VERSION 5.7 ;
BUSBITCHARS "[]" ;
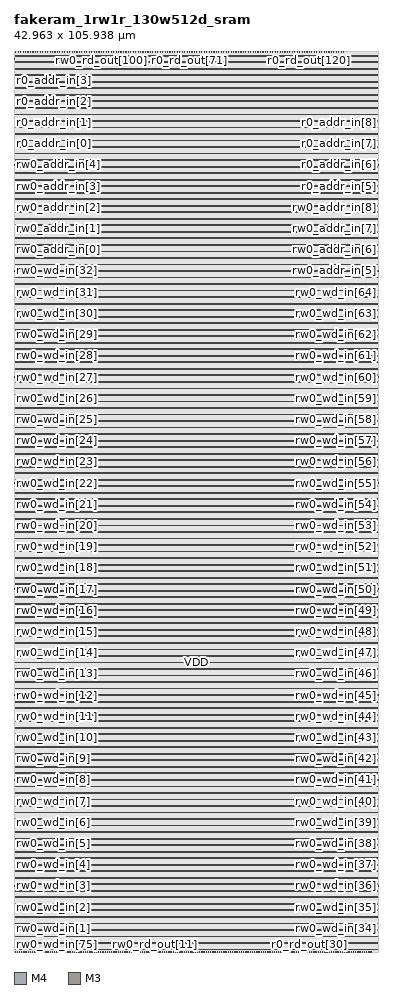
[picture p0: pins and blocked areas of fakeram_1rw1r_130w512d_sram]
MACRO fakeram_1rw1r_130w512d_sram
  FOREIGN fakeram_1rw1r_130w512d_sram 0 0 ;
  SYMMETRY X Y R90 ;
  SIZE 42.963 BY 105.938 ;
  CLASS BLOCK ;
  PIN rw0_wd_in[0]
    DIRECTION INPUT ;
    USE SIGNAL ;
    SHAPE ABUTMENT ;
    PORT
      LAYER M4 ;
      RECT 0.000 0.276 0.072 0.300 ;
    END
  END rw0_wd_in[0]
  PIN rw0_wd_in[1]
    DIRECTION INPUT ;
    USE SIGNAL ;
    SHAPE ABUTMENT ;
    PORT
      LAYER M4 ;
      RECT 0.000 2.772 0.072 2.796 ;
    END
  END rw0_wd_in[1]
  PIN rw0_wd_in[2]
    DIRECTION INPUT ;
    USE SIGNAL ;
    SHAPE ABUTMENT ;
    PORT
      LAYER M4 ;
      RECT 0.000 5.268 0.072 5.292 ;
    END
  END rw0_wd_in[2]
  PIN rw0_wd_in[3]
    DIRECTION INPUT ;
    USE SIGNAL ;
    SHAPE ABUTMENT ;
    PORT
      LAYER M4 ;
      RECT 0.000 7.764 0.072 7.788 ;
    END
  END rw0_wd_in[3]
  PIN rw0_wd_in[4]
    DIRECTION INPUT ;
    USE SIGNAL ;
    SHAPE ABUTMENT ;
    PORT
      LAYER M4 ;
      RECT 0.000 10.260 0.072 10.284 ;
    END
  END rw0_wd_in[4]
  PIN rw0_wd_in[5]
    DIRECTION INPUT ;
    USE SIGNAL ;
    SHAPE ABUTMENT ;
    PORT
      LAYER M4 ;
      RECT 0.000 12.756 0.072 12.780 ;
    END
  END rw0_wd_in[5]
  PIN rw0_wd_in[6]
    DIRECTION INPUT ;
    USE SIGNAL ;
    SHAPE ABUTMENT ;
    PORT
      LAYER M4 ;
      RECT 0.000 15.252 0.072 15.276 ;
    END
  END rw0_wd_in[6]
  PIN rw0_wd_in[7]
    DIRECTION INPUT ;
    USE SIGNAL ;
    SHAPE ABUTMENT ;
    PORT
      LAYER M4 ;
      RECT 0.000 17.748 0.072 17.772 ;
    END
  END rw0_wd_in[7]
  PIN rw0_wd_in[8]
    DIRECTION INPUT ;
    USE SIGNAL ;
    SHAPE ABUTMENT ;
    PORT
      LAYER M4 ;
      RECT 0.000 20.244 0.072 20.268 ;
    END
  END rw0_wd_in[8]
  PIN rw0_wd_in[9]
    DIRECTION INPUT ;
    USE SIGNAL ;
    SHAPE ABUTMENT ;
    PORT
      LAYER M4 ;
      RECT 0.000 22.740 0.072 22.764 ;
    END
  END rw0_wd_in[9]
  PIN rw0_wd_in[10]
    DIRECTION INPUT ;
    USE SIGNAL ;
    SHAPE ABUTMENT ;
    PORT
      LAYER M4 ;
      RECT 0.000 25.236 0.072 25.260 ;
    END
  END rw0_wd_in[10]
  PIN rw0_wd_in[11]
    DIRECTION INPUT ;
    USE SIGNAL ;
    SHAPE ABUTMENT ;
    PORT
      LAYER M4 ;
      RECT 0.000 27.732 0.072 27.756 ;
    END
  END rw0_wd_in[11]
  PIN rw0_wd_in[12]
    DIRECTION INPUT ;
    USE SIGNAL ;
    SHAPE ABUTMENT ;
    PORT
      LAYER M4 ;
      RECT 0.000 30.228 0.072 30.252 ;
    END
  END rw0_wd_in[12]
  PIN rw0_wd_in[13]
    DIRECTION INPUT ;
    USE SIGNAL ;
    SHAPE ABUTMENT ;
    PORT
      LAYER M4 ;
      RECT 0.000 32.724 0.072 32.748 ;
    END
  END rw0_wd_in[13]
  PIN rw0_wd_in[14]
    DIRECTION INPUT ;
    USE SIGNAL ;
    SHAPE ABUTMENT ;
    PORT
      LAYER M4 ;
      RECT 0.000 35.220 0.072 35.244 ;
    END
  END rw0_wd_in[14]
  PIN rw0_wd_in[15]
    DIRECTION INPUT ;
    USE SIGNAL ;
    SHAPE ABUTMENT ;
    PORT
      LAYER M4 ;
      RECT 0.000 37.716 0.072 37.740 ;
    END
  END rw0_wd_in[15]
  PIN rw0_wd_in[16]
    DIRECTION INPUT ;
    USE SIGNAL ;
    SHAPE ABUTMENT ;
    PORT
      LAYER M4 ;
      RECT 0.000 40.212 0.072 40.236 ;
    END
  END rw0_wd_in[16]
  PIN rw0_wd_in[17]
    DIRECTION INPUT ;
    USE SIGNAL ;
    SHAPE ABUTMENT ;
    PORT
      LAYER M4 ;
      RECT 0.000 42.708 0.072 42.732 ;
    END
  END rw0_wd_in[17]
  PIN rw0_wd_in[18]
    DIRECTION INPUT ;
    USE SIGNAL ;
    SHAPE ABUTMENT ;
    PORT
      LAYER M4 ;
      RECT 0.000 45.204 0.072 45.228 ;
    END
  END rw0_wd_in[18]
  PIN rw0_wd_in[19]
    DIRECTION INPUT ;
    USE SIGNAL ;
    SHAPE ABUTMENT ;
    PORT
      LAYER M4 ;
      RECT 0.000 47.700 0.072 47.724 ;
    END
  END rw0_wd_in[19]
  PIN rw0_wd_in[20]
    DIRECTION INPUT ;
    USE SIGNAL ;
    SHAPE ABUTMENT ;
    PORT
      LAYER M4 ;
      RECT 0.000 50.196 0.072 50.220 ;
    END
  END rw0_wd_in[20]
  PIN rw0_wd_in[21]
    DIRECTION INPUT ;
    USE SIGNAL ;
    SHAPE ABUTMENT ;
    PORT
      LAYER M4 ;
      RECT 0.000 52.692 0.072 52.716 ;
    END
  END rw0_wd_in[21]
  PIN rw0_wd_in[22]
    DIRECTION INPUT ;
    USE SIGNAL ;
    SHAPE ABUTMENT ;
    PORT
      LAYER M4 ;
      RECT 0.000 55.188 0.072 55.212 ;
    END
  END rw0_wd_in[22]
  PIN rw0_wd_in[23]
    DIRECTION INPUT ;
    USE SIGNAL ;
    SHAPE ABUTMENT ;
    PORT
      LAYER M4 ;
      RECT 0.000 57.684 0.072 57.708 ;
    END
  END rw0_wd_in[23]
  PIN rw0_wd_in[24]
    DIRECTION INPUT ;
    USE SIGNAL ;
    SHAPE ABUTMENT ;
    PORT
      LAYER M4 ;
      RECT 0.000 60.180 0.072 60.204 ;
    END
  END rw0_wd_in[24]
  PIN rw0_wd_in[25]
    DIRECTION INPUT ;
    USE SIGNAL ;
    SHAPE ABUTMENT ;
    PORT
      LAYER M4 ;
      RECT 0.000 62.676 0.072 62.700 ;
    END
  END rw0_wd_in[25]
  PIN rw0_wd_in[26]
    DIRECTION INPUT ;
    USE SIGNAL ;
    SHAPE ABUTMENT ;
    PORT
      LAYER M4 ;
      RECT 0.000 65.172 0.072 65.196 ;
    END
  END rw0_wd_in[26]
  PIN rw0_wd_in[27]
    DIRECTION INPUT ;
    USE SIGNAL ;
    SHAPE ABUTMENT ;
    PORT
      LAYER M4 ;
      RECT 0.000 67.668 0.072 67.692 ;
    END
  END rw0_wd_in[27]
  PIN rw0_wd_in[28]
    DIRECTION INPUT ;
    USE SIGNAL ;
    SHAPE ABUTMENT ;
    PORT
      LAYER M4 ;
      RECT 0.000 70.164 0.072 70.188 ;
    END
  END rw0_wd_in[28]
  PIN rw0_wd_in[29]
    DIRECTION INPUT ;
    USE SIGNAL ;
    SHAPE ABUTMENT ;
    PORT
      LAYER M4 ;
      RECT 0.000 72.660 0.072 72.684 ;
    END
  END rw0_wd_in[29]
  PIN rw0_wd_in[30]
    DIRECTION INPUT ;
    USE SIGNAL ;
    SHAPE ABUTMENT ;
    PORT
      LAYER M4 ;
      RECT 0.000 75.156 0.072 75.180 ;
    END
  END rw0_wd_in[30]
  PIN rw0_wd_in[31]
    DIRECTION INPUT ;
    USE SIGNAL ;
    SHAPE ABUTMENT ;
    PORT
      LAYER M4 ;
      RECT 0.000 77.652 0.072 77.676 ;
    END
  END rw0_wd_in[31]
  PIN rw0_wd_in[32]
    DIRECTION INPUT ;
    USE SIGNAL ;
    SHAPE ABUTMENT ;
    PORT
      LAYER M4 ;
      RECT 0.000 80.148 0.072 80.172 ;
    END
  END rw0_wd_in[32]
  PIN rw0_wd_in[33]
    DIRECTION INPUT ;
    USE SIGNAL ;
    SHAPE ABUTMENT ;
    PORT
      LAYER M4 ;
      RECT 42.891 0.276 42.963 0.300 ;
    END
  END rw0_wd_in[33]
  PIN rw0_wd_in[34]
    DIRECTION INPUT ;
    USE SIGNAL ;
    SHAPE ABUTMENT ;
    PORT
      LAYER M4 ;
      RECT 42.891 2.772 42.963 2.796 ;
    END
  END rw0_wd_in[34]
  PIN rw0_wd_in[35]
    DIRECTION INPUT ;
    USE SIGNAL ;
    SHAPE ABUTMENT ;
    PORT
      LAYER M4 ;
      RECT 42.891 5.268 42.963 5.292 ;
    END
  END rw0_wd_in[35]
  PIN rw0_wd_in[36]
    DIRECTION INPUT ;
    USE SIGNAL ;
    SHAPE ABUTMENT ;
    PORT
      LAYER M4 ;
      RECT 42.891 7.764 42.963 7.788 ;
    END
  END rw0_wd_in[36]
  PIN rw0_wd_in[37]
    DIRECTION INPUT ;
    USE SIGNAL ;
    SHAPE ABUTMENT ;
    PORT
      LAYER M4 ;
      RECT 42.891 10.260 42.963 10.284 ;
    END
  END rw0_wd_in[37]
  PIN rw0_wd_in[38]
    DIRECTION INPUT ;
    USE SIGNAL ;
    SHAPE ABUTMENT ;
    PORT
      LAYER M4 ;
      RECT 42.891 12.756 42.963 12.780 ;
    END
  END rw0_wd_in[38]
  PIN rw0_wd_in[39]
    DIRECTION INPUT ;
    USE SIGNAL ;
    SHAPE ABUTMENT ;
    PORT
      LAYER M4 ;
      RECT 42.891 15.252 42.963 15.276 ;
    END
  END rw0_wd_in[39]
  PIN rw0_wd_in[40]
    DIRECTION INPUT ;
    USE SIGNAL ;
    SHAPE ABUTMENT ;
    PORT
      LAYER M4 ;
      RECT 42.891 17.748 42.963 17.772 ;
    END
  END rw0_wd_in[40]
  PIN rw0_wd_in[41]
    DIRECTION INPUT ;
    USE SIGNAL ;
    SHAPE ABUTMENT ;
    PORT
      LAYER M4 ;
      RECT 42.891 20.244 42.963 20.268 ;
    END
  END rw0_wd_in[41]
  PIN rw0_wd_in[42]
    DIRECTION INPUT ;
    USE SIGNAL ;
    SHAPE ABUTMENT ;
    PORT
      LAYER M4 ;
      RECT 42.891 22.740 42.963 22.764 ;
    END
  END rw0_wd_in[42]
  PIN rw0_wd_in[43]
    DIRECTION INPUT ;
    USE SIGNAL ;
    SHAPE ABUTMENT ;
    PORT
      LAYER M4 ;
      RECT 42.891 25.236 42.963 25.260 ;
    END
  END rw0_wd_in[43]
  PIN rw0_wd_in[44]
    DIRECTION INPUT ;
    USE SIGNAL ;
    SHAPE ABUTMENT ;
    PORT
      LAYER M4 ;
      RECT 42.891 27.732 42.963 27.756 ;
    END
  END rw0_wd_in[44]
  PIN rw0_wd_in[45]
    DIRECTION INPUT ;
    USE SIGNAL ;
    SHAPE ABUTMENT ;
    PORT
      LAYER M4 ;
      RECT 42.891 30.228 42.963 30.252 ;
    END
  END rw0_wd_in[45]
  PIN rw0_wd_in[46]
    DIRECTION INPUT ;
    USE SIGNAL ;
    SHAPE ABUTMENT ;
    PORT
      LAYER M4 ;
      RECT 42.891 32.724 42.963 32.748 ;
    END
  END rw0_wd_in[46]
  PIN rw0_wd_in[47]
    DIRECTION INPUT ;
    USE SIGNAL ;
    SHAPE ABUTMENT ;
    PORT
      LAYER M4 ;
      RECT 42.891 35.220 42.963 35.244 ;
    END
  END rw0_wd_in[47]
  PIN rw0_wd_in[48]
    DIRECTION INPUT ;
    USE SIGNAL ;
    SHAPE ABUTMENT ;
    PORT
      LAYER M4 ;
      RECT 42.891 37.716 42.963 37.740 ;
    END
  END rw0_wd_in[48]
  PIN rw0_wd_in[49]
    DIRECTION INPUT ;
    USE SIGNAL ;
    SHAPE ABUTMENT ;
    PORT
      LAYER M4 ;
      RECT 42.891 40.212 42.963 40.236 ;
    END
  END rw0_wd_in[49]
  PIN rw0_wd_in[50]
    DIRECTION INPUT ;
    USE SIGNAL ;
    SHAPE ABUTMENT ;
    PORT
      LAYER M4 ;
      RECT 42.891 42.708 42.963 42.732 ;
    END
  END rw0_wd_in[50]
  PIN rw0_wd_in[51]
    DIRECTION INPUT ;
    USE SIGNAL ;
    SHAPE ABUTMENT ;
    PORT
      LAYER M4 ;
      RECT 42.891 45.204 42.963 45.228 ;
    END
  END rw0_wd_in[51]
  PIN rw0_wd_in[52]
    DIRECTION INPUT ;
    USE SIGNAL ;
    SHAPE ABUTMENT ;
    PORT
      LAYER M4 ;
      RECT 42.891 47.700 42.963 47.724 ;
    END
  END rw0_wd_in[52]
  PIN rw0_wd_in[53]
    DIRECTION INPUT ;
    USE SIGNAL ;
    SHAPE ABUTMENT ;
    PORT
      LAYER M4 ;
      RECT 42.891 50.196 42.963 50.220 ;
    END
  END rw0_wd_in[53]
  PIN rw0_wd_in[54]
    DIRECTION INPUT ;
    USE SIGNAL ;
    SHAPE ABUTMENT ;
    PORT
      LAYER M4 ;
      RECT 42.891 52.692 42.963 52.716 ;
    END
  END rw0_wd_in[54]
  PIN rw0_wd_in[55]
    DIRECTION INPUT ;
    USE SIGNAL ;
    SHAPE ABUTMENT ;
    PORT
      LAYER M4 ;
      RECT 42.891 55.188 42.963 55.212 ;
    END
  END rw0_wd_in[55]
  PIN rw0_wd_in[56]
    DIRECTION INPUT ;
    USE SIGNAL ;
    SHAPE ABUTMENT ;
    PORT
      LAYER M4 ;
      RECT 42.891 57.684 42.963 57.708 ;
    END
  END rw0_wd_in[56]
  PIN rw0_wd_in[57]
    DIRECTION INPUT ;
    USE SIGNAL ;
    SHAPE ABUTMENT ;
    PORT
      LAYER M4 ;
      RECT 42.891 60.180 42.963 60.204 ;
    END
  END rw0_wd_in[57]
  PIN rw0_wd_in[58]
    DIRECTION INPUT ;
    USE SIGNAL ;
    SHAPE ABUTMENT ;
    PORT
      LAYER M4 ;
      RECT 42.891 62.676 42.963 62.700 ;
    END
  END rw0_wd_in[58]
  PIN rw0_wd_in[59]
    DIRECTION INPUT ;
    USE SIGNAL ;
    SHAPE ABUTMENT ;
    PORT
      LAYER M4 ;
      RECT 42.891 65.172 42.963 65.196 ;
    END
  END rw0_wd_in[59]
  PIN rw0_wd_in[60]
    DIRECTION INPUT ;
    USE SIGNAL ;
    SHAPE ABUTMENT ;
    PORT
      LAYER M4 ;
      RECT 42.891 67.668 42.963 67.692 ;
    END
  END rw0_wd_in[60]
  PIN rw0_wd_in[61]
    DIRECTION INPUT ;
    USE SIGNAL ;
    SHAPE ABUTMENT ;
    PORT
      LAYER M4 ;
      RECT 42.891 70.164 42.963 70.188 ;
    END
  END rw0_wd_in[61]
  PIN rw0_wd_in[62]
    DIRECTION INPUT ;
    USE SIGNAL ;
    SHAPE ABUTMENT ;
    PORT
      LAYER M4 ;
      RECT 42.891 72.660 42.963 72.684 ;
    END
  END rw0_wd_in[62]
  PIN rw0_wd_in[63]
    DIRECTION INPUT ;
    USE SIGNAL ;
    SHAPE ABUTMENT ;
    PORT
      LAYER M4 ;
      RECT 42.891 75.156 42.963 75.180 ;
    END
  END rw0_wd_in[63]
  PIN rw0_wd_in[64]
    DIRECTION INPUT ;
    USE SIGNAL ;
    SHAPE ABUTMENT ;
    PORT
      LAYER M4 ;
      RECT 42.891 77.652 42.963 77.676 ;
    END
  END rw0_wd_in[64]
  PIN rw0_wd_in[65]
    DIRECTION OUTPUT ;
    USE SIGNAL ;
    SHAPE ABUTMENT ;
    PORT
      LAYER M3 ;
      RECT 0.207 0.000 0.225 0.054 ;
    END
  END rw0_wd_in[65]
  PIN rw0_wd_in[66]
    DIRECTION OUTPUT ;
    USE SIGNAL ;
    SHAPE ABUTMENT ;
    PORT
      LAYER M3 ;
      RECT 0.423 0.000 0.441 0.054 ;
    END
  END rw0_wd_in[66]
  PIN rw0_wd_in[67]
    DIRECTION OUTPUT ;
    USE SIGNAL ;
    SHAPE ABUTMENT ;
    PORT
      LAYER M3 ;
      RECT 0.639 0.000 0.657 0.054 ;
    END
  END rw0_wd_in[67]
  PIN rw0_wd_in[68]
    DIRECTION OUTPUT ;
    USE SIGNAL ;
    SHAPE ABUTMENT ;
    PORT
      LAYER M3 ;
      RECT 0.855 0.000 0.873 0.054 ;
    END
  END rw0_wd_in[68]
  PIN rw0_wd_in[69]
    DIRECTION OUTPUT ;
    USE SIGNAL ;
    SHAPE ABUTMENT ;
    PORT
      LAYER M3 ;
      RECT 1.071 0.000 1.089 0.054 ;
    END
  END rw0_wd_in[69]
  PIN rw0_wd_in[70]
    DIRECTION OUTPUT ;
    USE SIGNAL ;
    SHAPE ABUTMENT ;
    PORT
      LAYER M3 ;
      RECT 1.287 0.000 1.305 0.054 ;
    END
  END rw0_wd_in[70]
  PIN rw0_wd_in[71]
    DIRECTION OUTPUT ;
    USE SIGNAL ;
    SHAPE ABUTMENT ;
    PORT
      LAYER M3 ;
      RECT 1.503 0.000 1.521 0.054 ;
    END
  END rw0_wd_in[71]
  PIN rw0_wd_in[72]
    DIRECTION OUTPUT ;
    USE SIGNAL ;
    SHAPE ABUTMENT ;
    PORT
      LAYER M3 ;
      RECT 1.719 0.000 1.737 0.054 ;
    END
  END rw0_wd_in[72]
  PIN rw0_wd_in[73]
    DIRECTION OUTPUT ;
    USE SIGNAL ;
    SHAPE ABUTMENT ;
    PORT
      LAYER M3 ;
      RECT 1.935 0.000 1.953 0.054 ;
    END
  END rw0_wd_in[73]
  PIN rw0_wd_in[74]
    DIRECTION OUTPUT ;
    USE SIGNAL ;
    SHAPE ABUTMENT ;
    PORT
      LAYER M3 ;
      RECT 2.151 0.000 2.169 0.054 ;
    END
  END rw0_wd_in[74]
  PIN rw0_wd_in[75]
    DIRECTION OUTPUT ;
    USE SIGNAL ;
    SHAPE ABUTMENT ;
    PORT
      LAYER M3 ;
      RECT 2.367 0.000 2.385 0.054 ;
    END
  END rw0_wd_in[75]
  PIN rw0_wd_in[76]
    DIRECTION OUTPUT ;
    USE SIGNAL ;
    SHAPE ABUTMENT ;
    PORT
      LAYER M3 ;
      RECT 2.583 0.000 2.601 0.054 ;
    END
  END rw0_wd_in[76]
  PIN rw0_wd_in[77]
    DIRECTION OUTPUT ;
    USE SIGNAL ;
    SHAPE ABUTMENT ;
    PORT
      LAYER M3 ;
      RECT 2.799 0.000 2.817 0.054 ;
    END
  END rw0_wd_in[77]
  PIN rw0_wd_in[78]
    DIRECTION OUTPUT ;
    USE SIGNAL ;
    SHAPE ABUTMENT ;
    PORT
      LAYER M3 ;
      RECT 3.015 0.000 3.033 0.054 ;
    END
  END rw0_wd_in[78]
  PIN rw0_wd_in[79]
    DIRECTION OUTPUT ;
    USE SIGNAL ;
    SHAPE ABUTMENT ;
    PORT
      LAYER M3 ;
      RECT 3.231 0.000 3.249 0.054 ;
    END
  END rw0_wd_in[79]
  PIN rw0_wd_in[80]
    DIRECTION OUTPUT ;
    USE SIGNAL ;
    SHAPE ABUTMENT ;
    PORT
      LAYER M3 ;
      RECT 3.447 0.000 3.465 0.054 ;
    END
  END rw0_wd_in[80]
  PIN rw0_wd_in[81]
    DIRECTION OUTPUT ;
    USE SIGNAL ;
    SHAPE ABUTMENT ;
    PORT
      LAYER M3 ;
      RECT 3.663 0.000 3.681 0.054 ;
    END
  END rw0_wd_in[81]
  PIN rw0_wd_in[82]
    DIRECTION OUTPUT ;
    USE SIGNAL ;
    SHAPE ABUTMENT ;
    PORT
      LAYER M3 ;
      RECT 3.879 0.000 3.897 0.054 ;
    END
  END rw0_wd_in[82]
  PIN rw0_wd_in[83]
    DIRECTION OUTPUT ;
    USE SIGNAL ;
    SHAPE ABUTMENT ;
    PORT
      LAYER M3 ;
      RECT 4.095 0.000 4.113 0.054 ;
    END
  END rw0_wd_in[83]
  PIN rw0_wd_in[84]
    DIRECTION OUTPUT ;
    USE SIGNAL ;
    SHAPE ABUTMENT ;
    PORT
      LAYER M3 ;
      RECT 4.311 0.000 4.329 0.054 ;
    END
  END rw0_wd_in[84]
  PIN rw0_wd_in[85]
    DIRECTION OUTPUT ;
    USE SIGNAL ;
    SHAPE ABUTMENT ;
    PORT
      LAYER M3 ;
      RECT 4.527 0.000 4.545 0.054 ;
    END
  END rw0_wd_in[85]
  PIN rw0_wd_in[86]
    DIRECTION OUTPUT ;
    USE SIGNAL ;
    SHAPE ABUTMENT ;
    PORT
      LAYER M3 ;
      RECT 4.743 0.000 4.761 0.054 ;
    END
  END rw0_wd_in[86]
  PIN rw0_wd_in[87]
    DIRECTION OUTPUT ;
    USE SIGNAL ;
    SHAPE ABUTMENT ;
    PORT
      LAYER M3 ;
      RECT 4.959 0.000 4.977 0.054 ;
    END
  END rw0_wd_in[87]
  PIN rw0_wd_in[88]
    DIRECTION OUTPUT ;
    USE SIGNAL ;
    SHAPE ABUTMENT ;
    PORT
      LAYER M3 ;
      RECT 5.175 0.000 5.193 0.054 ;
    END
  END rw0_wd_in[88]
  PIN rw0_wd_in[89]
    DIRECTION OUTPUT ;
    USE SIGNAL ;
    SHAPE ABUTMENT ;
    PORT
      LAYER M3 ;
      RECT 5.391 0.000 5.409 0.054 ;
    END
  END rw0_wd_in[89]
  PIN rw0_wd_in[90]
    DIRECTION OUTPUT ;
    USE SIGNAL ;
    SHAPE ABUTMENT ;
    PORT
      LAYER M3 ;
      RECT 5.607 0.000 5.625 0.054 ;
    END
  END rw0_wd_in[90]
  PIN rw0_wd_in[91]
    DIRECTION OUTPUT ;
    USE SIGNAL ;
    SHAPE ABUTMENT ;
    PORT
      LAYER M3 ;
      RECT 5.823 0.000 5.841 0.054 ;
    END
  END rw0_wd_in[91]
  PIN rw0_wd_in[92]
    DIRECTION OUTPUT ;
    USE SIGNAL ;
    SHAPE ABUTMENT ;
    PORT
      LAYER M3 ;
      RECT 6.039 0.000 6.057 0.054 ;
    END
  END rw0_wd_in[92]
  PIN rw0_wd_in[93]
    DIRECTION OUTPUT ;
    USE SIGNAL ;
    SHAPE ABUTMENT ;
    PORT
      LAYER M3 ;
      RECT 6.255 0.000 6.273 0.054 ;
    END
  END rw0_wd_in[93]
  PIN rw0_wd_in[94]
    DIRECTION OUTPUT ;
    USE SIGNAL ;
    SHAPE ABUTMENT ;
    PORT
      LAYER M3 ;
      RECT 6.471 0.000 6.489 0.054 ;
    END
  END rw0_wd_in[94]
  PIN rw0_wd_in[95]
    DIRECTION OUTPUT ;
    USE SIGNAL ;
    SHAPE ABUTMENT ;
    PORT
      LAYER M3 ;
      RECT 6.687 0.000 6.705 0.054 ;
    END
  END rw0_wd_in[95]
  PIN rw0_wd_in[96]
    DIRECTION OUTPUT ;
    USE SIGNAL ;
    SHAPE ABUTMENT ;
    PORT
      LAYER M3 ;
      RECT 6.903 0.000 6.921 0.054 ;
    END
  END rw0_wd_in[96]
  PIN rw0_wd_in[97]
    DIRECTION OUTPUT ;
    USE SIGNAL ;
    SHAPE ABUTMENT ;
    PORT
      LAYER M3 ;
      RECT 7.119 0.000 7.137 0.054 ;
    END
  END rw0_wd_in[97]
  PIN rw0_wd_in[98]
    DIRECTION OUTPUT ;
    USE SIGNAL ;
    SHAPE ABUTMENT ;
    PORT
      LAYER M3 ;
      RECT 7.335 0.000 7.353 0.054 ;
    END
  END rw0_wd_in[98]
  PIN rw0_wd_in[99]
    DIRECTION OUTPUT ;
    USE SIGNAL ;
    SHAPE ABUTMENT ;
    PORT
      LAYER M3 ;
      RECT 7.551 0.000 7.569 0.054 ;
    END
  END rw0_wd_in[99]
  PIN rw0_wd_in[100]
    DIRECTION OUTPUT ;
    USE SIGNAL ;
    SHAPE ABUTMENT ;
    PORT
      LAYER M3 ;
      RECT 7.767 0.000 7.785 0.054 ;
    END
  END rw0_wd_in[100]
  PIN rw0_wd_in[101]
    DIRECTION OUTPUT ;
    USE SIGNAL ;
    SHAPE ABUTMENT ;
    PORT
      LAYER M3 ;
      RECT 7.983 0.000 8.001 0.054 ;
    END
  END rw0_wd_in[101]
  PIN rw0_wd_in[102]
    DIRECTION OUTPUT ;
    USE SIGNAL ;
    SHAPE ABUTMENT ;
    PORT
      LAYER M3 ;
      RECT 8.199 0.000 8.217 0.054 ;
    END
  END rw0_wd_in[102]
  PIN rw0_wd_in[103]
    DIRECTION OUTPUT ;
    USE SIGNAL ;
    SHAPE ABUTMENT ;
    PORT
      LAYER M3 ;
      RECT 8.415 0.000 8.433 0.054 ;
    END
  END rw0_wd_in[103]
  PIN rw0_wd_in[104]
    DIRECTION OUTPUT ;
    USE SIGNAL ;
    SHAPE ABUTMENT ;
    PORT
      LAYER M3 ;
      RECT 8.631 0.000 8.649 0.054 ;
    END
  END rw0_wd_in[104]
  PIN rw0_wd_in[105]
    DIRECTION OUTPUT ;
    USE SIGNAL ;
    SHAPE ABUTMENT ;
    PORT
      LAYER M3 ;
      RECT 8.847 0.000 8.865 0.054 ;
    END
  END rw0_wd_in[105]
  PIN rw0_wd_in[106]
    DIRECTION OUTPUT ;
    USE SIGNAL ;
    SHAPE ABUTMENT ;
    PORT
      LAYER M3 ;
      RECT 9.063 0.000 9.081 0.054 ;
    END
  END rw0_wd_in[106]
  PIN rw0_wd_in[107]
    DIRECTION OUTPUT ;
    USE SIGNAL ;
    SHAPE ABUTMENT ;
    PORT
      LAYER M3 ;
      RECT 9.279 0.000 9.297 0.054 ;
    END
  END rw0_wd_in[107]
  PIN rw0_wd_in[108]
    DIRECTION OUTPUT ;
    USE SIGNAL ;
    SHAPE ABUTMENT ;
    PORT
      LAYER M3 ;
      RECT 9.495 0.000 9.513 0.054 ;
    END
  END rw0_wd_in[108]
  PIN rw0_wd_in[109]
    DIRECTION OUTPUT ;
    USE SIGNAL ;
    SHAPE ABUTMENT ;
    PORT
      LAYER M3 ;
      RECT 9.711 0.000 9.729 0.054 ;
    END
  END rw0_wd_in[109]
  PIN rw0_wd_in[110]
    DIRECTION OUTPUT ;
    USE SIGNAL ;
    SHAPE ABUTMENT ;
    PORT
      LAYER M3 ;
      RECT 9.927 0.000 9.945 0.054 ;
    END
  END rw0_wd_in[110]
  PIN rw0_wd_in[111]
    DIRECTION OUTPUT ;
    USE SIGNAL ;
    SHAPE ABUTMENT ;
    PORT
      LAYER M3 ;
      RECT 10.143 0.000 10.161 0.054 ;
    END
  END rw0_wd_in[111]
  PIN rw0_wd_in[112]
    DIRECTION OUTPUT ;
    USE SIGNAL ;
    SHAPE ABUTMENT ;
    PORT
      LAYER M3 ;
      RECT 10.359 0.000 10.377 0.054 ;
    END
  END rw0_wd_in[112]
  PIN rw0_wd_in[113]
    DIRECTION OUTPUT ;
    USE SIGNAL ;
    SHAPE ABUTMENT ;
    PORT
      LAYER M3 ;
      RECT 10.575 0.000 10.593 0.054 ;
    END
  END rw0_wd_in[113]
  PIN rw0_wd_in[114]
    DIRECTION OUTPUT ;
    USE SIGNAL ;
    SHAPE ABUTMENT ;
    PORT
      LAYER M3 ;
      RECT 10.791 0.000 10.809 0.054 ;
    END
  END rw0_wd_in[114]
  PIN rw0_wd_in[115]
    DIRECTION OUTPUT ;
    USE SIGNAL ;
    SHAPE ABUTMENT ;
    PORT
      LAYER M3 ;
      RECT 11.007 0.000 11.025 0.054 ;
    END
  END rw0_wd_in[115]
  PIN rw0_wd_in[116]
    DIRECTION OUTPUT ;
    USE SIGNAL ;
    SHAPE ABUTMENT ;
    PORT
      LAYER M3 ;
      RECT 11.223 0.000 11.241 0.054 ;
    END
  END rw0_wd_in[116]
  PIN rw0_wd_in[117]
    DIRECTION OUTPUT ;
    USE SIGNAL ;
    SHAPE ABUTMENT ;
    PORT
      LAYER M3 ;
      RECT 11.439 0.000 11.457 0.054 ;
    END
  END rw0_wd_in[117]
  PIN rw0_wd_in[118]
    DIRECTION OUTPUT ;
    USE SIGNAL ;
    SHAPE ABUTMENT ;
    PORT
      LAYER M3 ;
      RECT 11.655 0.000 11.673 0.054 ;
    END
  END rw0_wd_in[118]
  PIN rw0_wd_in[119]
    DIRECTION OUTPUT ;
    USE SIGNAL ;
    SHAPE ABUTMENT ;
    PORT
      LAYER M3 ;
      RECT 11.871 0.000 11.889 0.054 ;
    END
  END rw0_wd_in[119]
  PIN rw0_wd_in[120]
    DIRECTION OUTPUT ;
    USE SIGNAL ;
    SHAPE ABUTMENT ;
    PORT
      LAYER M3 ;
      RECT 12.087 0.000 12.105 0.054 ;
    END
  END rw0_wd_in[120]
  PIN rw0_wd_in[121]
    DIRECTION OUTPUT ;
    USE SIGNAL ;
    SHAPE ABUTMENT ;
    PORT
      LAYER M3 ;
      RECT 12.303 0.000 12.321 0.054 ;
    END
  END rw0_wd_in[121]
  PIN rw0_wd_in[122]
    DIRECTION OUTPUT ;
    USE SIGNAL ;
    SHAPE ABUTMENT ;
    PORT
      LAYER M3 ;
      RECT 12.519 0.000 12.537 0.054 ;
    END
  END rw0_wd_in[122]
  PIN rw0_wd_in[123]
    DIRECTION OUTPUT ;
    USE SIGNAL ;
    SHAPE ABUTMENT ;
    PORT
      LAYER M3 ;
      RECT 12.735 0.000 12.753 0.054 ;
    END
  END rw0_wd_in[123]
  PIN rw0_wd_in[124]
    DIRECTION OUTPUT ;
    USE SIGNAL ;
    SHAPE ABUTMENT ;
    PORT
      LAYER M3 ;
      RECT 12.951 0.000 12.969 0.054 ;
    END
  END rw0_wd_in[124]
  PIN rw0_wd_in[125]
    DIRECTION OUTPUT ;
    USE SIGNAL ;
    SHAPE ABUTMENT ;
    PORT
      LAYER M3 ;
      RECT 13.167 0.000 13.185 0.054 ;
    END
  END rw0_wd_in[125]
  PIN rw0_wd_in[126]
    DIRECTION OUTPUT ;
    USE SIGNAL ;
    SHAPE ABUTMENT ;
    PORT
      LAYER M3 ;
      RECT 13.383 0.000 13.401 0.054 ;
    END
  END rw0_wd_in[126]
  PIN rw0_wd_in[127]
    DIRECTION OUTPUT ;
    USE SIGNAL ;
    SHAPE ABUTMENT ;
    PORT
      LAYER M3 ;
      RECT 13.599 0.000 13.617 0.054 ;
    END
  END rw0_wd_in[127]
  PIN rw0_wd_in[128]
    DIRECTION OUTPUT ;
    USE SIGNAL ;
    SHAPE ABUTMENT ;
    PORT
      LAYER M3 ;
      RECT 13.815 0.000 13.833 0.054 ;
    END
  END rw0_wd_in[128]
  PIN rw0_wd_in[129]
    DIRECTION OUTPUT ;
    USE SIGNAL ;
    SHAPE ABUTMENT ;
    PORT
      LAYER M3 ;
      RECT 14.031 0.000 14.049 0.054 ;
    END
  END rw0_wd_in[129]
  PIN rw0_rd_out[0]
    DIRECTION OUTPUT ;
    USE SIGNAL ;
    SHAPE ABUTMENT ;
    PORT
      LAYER M3 ;
      RECT 14.247 0.000 14.265 0.054 ;
    END
  END rw0_rd_out[0]
  PIN rw0_rd_out[1]
    DIRECTION OUTPUT ;
    USE SIGNAL ;
    SHAPE ABUTMENT ;
    PORT
      LAYER M3 ;
      RECT 14.463 0.000 14.481 0.054 ;
    END
  END rw0_rd_out[1]
  PIN rw0_rd_out[2]
    DIRECTION OUTPUT ;
    USE SIGNAL ;
    SHAPE ABUTMENT ;
    PORT
      LAYER M3 ;
      RECT 14.679 0.000 14.697 0.054 ;
    END
  END rw0_rd_out[2]
  PIN rw0_rd_out[3]
    DIRECTION OUTPUT ;
    USE SIGNAL ;
    SHAPE ABUTMENT ;
    PORT
      LAYER M3 ;
      RECT 14.895 0.000 14.913 0.054 ;
    END
  END rw0_rd_out[3]
  PIN rw0_rd_out[4]
    DIRECTION OUTPUT ;
    USE SIGNAL ;
    SHAPE ABUTMENT ;
    PORT
      LAYER M3 ;
      RECT 15.111 0.000 15.129 0.054 ;
    END
  END rw0_rd_out[4]
  PIN rw0_rd_out[5]
    DIRECTION OUTPUT ;
    USE SIGNAL ;
    SHAPE ABUTMENT ;
    PORT
      LAYER M3 ;
      RECT 15.327 0.000 15.345 0.054 ;
    END
  END rw0_rd_out[5]
  PIN rw0_rd_out[6]
    DIRECTION OUTPUT ;
    USE SIGNAL ;
    SHAPE ABUTMENT ;
    PORT
      LAYER M3 ;
      RECT 15.543 0.000 15.561 0.054 ;
    END
  END rw0_rd_out[6]
  PIN rw0_rd_out[7]
    DIRECTION OUTPUT ;
    USE SIGNAL ;
    SHAPE ABUTMENT ;
    PORT
      LAYER M3 ;
      RECT 15.759 0.000 15.777 0.054 ;
    END
  END rw0_rd_out[7]
  PIN rw0_rd_out[8]
    DIRECTION OUTPUT ;
    USE SIGNAL ;
    SHAPE ABUTMENT ;
    PORT
      LAYER M3 ;
      RECT 15.975 0.000 15.993 0.054 ;
    END
  END rw0_rd_out[8]
  PIN rw0_rd_out[9]
    DIRECTION OUTPUT ;
    USE SIGNAL ;
    SHAPE ABUTMENT ;
    PORT
      LAYER M3 ;
      RECT 16.191 0.000 16.209 0.054 ;
    END
  END rw0_rd_out[9]
  PIN rw0_rd_out[10]
    DIRECTION OUTPUT ;
    USE SIGNAL ;
    SHAPE ABUTMENT ;
    PORT
      LAYER M3 ;
      RECT 16.407 0.000 16.425 0.054 ;
    END
  END rw0_rd_out[10]
  PIN rw0_rd_out[11]
    DIRECTION OUTPUT ;
    USE SIGNAL ;
    SHAPE ABUTMENT ;
    PORT
      LAYER M3 ;
      RECT 16.623 0.000 16.641 0.054 ;
    END
  END rw0_rd_out[11]
  PIN rw0_rd_out[12]
    DIRECTION OUTPUT ;
    USE SIGNAL ;
    SHAPE ABUTMENT ;
    PORT
      LAYER M3 ;
      RECT 16.839 0.000 16.857 0.054 ;
    END
  END rw0_rd_out[12]
  PIN rw0_rd_out[13]
    DIRECTION OUTPUT ;
    USE SIGNAL ;
    SHAPE ABUTMENT ;
    PORT
      LAYER M3 ;
      RECT 17.055 0.000 17.073 0.054 ;
    END
  END rw0_rd_out[13]
  PIN rw0_rd_out[14]
    DIRECTION OUTPUT ;
    USE SIGNAL ;
    SHAPE ABUTMENT ;
    PORT
      LAYER M3 ;
      RECT 17.271 0.000 17.289 0.054 ;
    END
  END rw0_rd_out[14]
  PIN rw0_rd_out[15]
    DIRECTION OUTPUT ;
    USE SIGNAL ;
    SHAPE ABUTMENT ;
    PORT
      LAYER M3 ;
      RECT 17.487 0.000 17.505 0.054 ;
    END
  END rw0_rd_out[15]
  PIN rw0_rd_out[16]
    DIRECTION OUTPUT ;
    USE SIGNAL ;
    SHAPE ABUTMENT ;
    PORT
      LAYER M3 ;
      RECT 17.703 0.000 17.721 0.054 ;
    END
  END rw0_rd_out[16]
  PIN rw0_rd_out[17]
    DIRECTION OUTPUT ;
    USE SIGNAL ;
    SHAPE ABUTMENT ;
    PORT
      LAYER M3 ;
      RECT 17.919 0.000 17.937 0.054 ;
    END
  END rw0_rd_out[17]
  PIN rw0_rd_out[18]
    DIRECTION OUTPUT ;
    USE SIGNAL ;
    SHAPE ABUTMENT ;
    PORT
      LAYER M3 ;
      RECT 18.135 0.000 18.153 0.054 ;
    END
  END rw0_rd_out[18]
  PIN rw0_rd_out[19]
    DIRECTION OUTPUT ;
    USE SIGNAL ;
    SHAPE ABUTMENT ;
    PORT
      LAYER M3 ;
      RECT 18.351 0.000 18.369 0.054 ;
    END
  END rw0_rd_out[19]
  PIN rw0_rd_out[20]
    DIRECTION OUTPUT ;
    USE SIGNAL ;
    SHAPE ABUTMENT ;
    PORT
      LAYER M3 ;
      RECT 18.567 0.000 18.585 0.054 ;
    END
  END rw0_rd_out[20]
  PIN rw0_rd_out[21]
    DIRECTION OUTPUT ;
    USE SIGNAL ;
    SHAPE ABUTMENT ;
    PORT
      LAYER M3 ;
      RECT 18.783 0.000 18.801 0.054 ;
    END
  END rw0_rd_out[21]
  PIN rw0_rd_out[22]
    DIRECTION OUTPUT ;
    USE SIGNAL ;
    SHAPE ABUTMENT ;
    PORT
      LAYER M3 ;
      RECT 18.999 0.000 19.017 0.054 ;
    END
  END rw0_rd_out[22]
  PIN rw0_rd_out[23]
    DIRECTION OUTPUT ;
    USE SIGNAL ;
    SHAPE ABUTMENT ;
    PORT
      LAYER M3 ;
      RECT 19.215 0.000 19.233 0.054 ;
    END
  END rw0_rd_out[23]
  PIN rw0_rd_out[24]
    DIRECTION OUTPUT ;
    USE SIGNAL ;
    SHAPE ABUTMENT ;
    PORT
      LAYER M3 ;
      RECT 19.431 0.000 19.449 0.054 ;
    END
  END rw0_rd_out[24]
  PIN rw0_rd_out[25]
    DIRECTION OUTPUT ;
    USE SIGNAL ;
    SHAPE ABUTMENT ;
    PORT
      LAYER M3 ;
      RECT 19.647 0.000 19.665 0.054 ;
    END
  END rw0_rd_out[25]
  PIN rw0_rd_out[26]
    DIRECTION OUTPUT ;
    USE SIGNAL ;
    SHAPE ABUTMENT ;
    PORT
      LAYER M3 ;
      RECT 19.863 0.000 19.881 0.054 ;
    END
  END rw0_rd_out[26]
  PIN rw0_rd_out[27]
    DIRECTION OUTPUT ;
    USE SIGNAL ;
    SHAPE ABUTMENT ;
    PORT
      LAYER M3 ;
      RECT 20.079 0.000 20.097 0.054 ;
    END
  END rw0_rd_out[27]
  PIN rw0_rd_out[28]
    DIRECTION OUTPUT ;
    USE SIGNAL ;
    SHAPE ABUTMENT ;
    PORT
      LAYER M3 ;
      RECT 20.295 0.000 20.313 0.054 ;
    END
  END rw0_rd_out[28]
  PIN rw0_rd_out[29]
    DIRECTION OUTPUT ;
    USE SIGNAL ;
    SHAPE ABUTMENT ;
    PORT
      LAYER M3 ;
      RECT 20.511 0.000 20.529 0.054 ;
    END
  END rw0_rd_out[29]
  PIN rw0_rd_out[30]
    DIRECTION OUTPUT ;
    USE SIGNAL ;
    SHAPE ABUTMENT ;
    PORT
      LAYER M3 ;
      RECT 20.727 0.000 20.745 0.054 ;
    END
  END rw0_rd_out[30]
  PIN rw0_rd_out[31]
    DIRECTION OUTPUT ;
    USE SIGNAL ;
    SHAPE ABUTMENT ;
    PORT
      LAYER M3 ;
      RECT 20.943 0.000 20.961 0.054 ;
    END
  END rw0_rd_out[31]
  PIN rw0_rd_out[32]
    DIRECTION OUTPUT ;
    USE SIGNAL ;
    SHAPE ABUTMENT ;
    PORT
      LAYER M3 ;
      RECT 21.159 0.000 21.177 0.054 ;
    END
  END rw0_rd_out[32]
  PIN rw0_rd_out[33]
    DIRECTION OUTPUT ;
    USE SIGNAL ;
    SHAPE ABUTMENT ;
    PORT
      LAYER M3 ;
      RECT 21.375 0.000 21.393 0.054 ;
    END
  END rw0_rd_out[33]
  PIN rw0_rd_out[34]
    DIRECTION OUTPUT ;
    USE SIGNAL ;
    SHAPE ABUTMENT ;
    PORT
      LAYER M3 ;
      RECT 21.591 0.000 21.609 0.054 ;
    END
  END rw0_rd_out[34]
  PIN rw0_rd_out[35]
    DIRECTION OUTPUT ;
    USE SIGNAL ;
    SHAPE ABUTMENT ;
    PORT
      LAYER M3 ;
      RECT 21.807 0.000 21.825 0.054 ;
    END
  END rw0_rd_out[35]
  PIN rw0_rd_out[36]
    DIRECTION OUTPUT ;
    USE SIGNAL ;
    SHAPE ABUTMENT ;
    PORT
      LAYER M3 ;
      RECT 22.023 0.000 22.041 0.054 ;
    END
  END rw0_rd_out[36]
  PIN rw0_rd_out[37]
    DIRECTION OUTPUT ;
    USE SIGNAL ;
    SHAPE ABUTMENT ;
    PORT
      LAYER M3 ;
      RECT 22.239 0.000 22.257 0.054 ;
    END
  END rw0_rd_out[37]
  PIN rw0_rd_out[38]
    DIRECTION OUTPUT ;
    USE SIGNAL ;
    SHAPE ABUTMENT ;
    PORT
      LAYER M3 ;
      RECT 22.455 0.000 22.473 0.054 ;
    END
  END rw0_rd_out[38]
  PIN rw0_rd_out[39]
    DIRECTION OUTPUT ;
    USE SIGNAL ;
    SHAPE ABUTMENT ;
    PORT
      LAYER M3 ;
      RECT 22.671 0.000 22.689 0.054 ;
    END
  END rw0_rd_out[39]
  PIN rw0_rd_out[40]
    DIRECTION OUTPUT ;
    USE SIGNAL ;
    SHAPE ABUTMENT ;
    PORT
      LAYER M3 ;
      RECT 22.887 0.000 22.905 0.054 ;
    END
  END rw0_rd_out[40]
  PIN rw0_rd_out[41]
    DIRECTION OUTPUT ;
    USE SIGNAL ;
    SHAPE ABUTMENT ;
    PORT
      LAYER M3 ;
      RECT 23.103 0.000 23.121 0.054 ;
    END
  END rw0_rd_out[41]
  PIN rw0_rd_out[42]
    DIRECTION OUTPUT ;
    USE SIGNAL ;
    SHAPE ABUTMENT ;
    PORT
      LAYER M3 ;
      RECT 23.319 0.000 23.337 0.054 ;
    END
  END rw0_rd_out[42]
  PIN rw0_rd_out[43]
    DIRECTION OUTPUT ;
    USE SIGNAL ;
    SHAPE ABUTMENT ;
    PORT
      LAYER M3 ;
      RECT 23.535 0.000 23.553 0.054 ;
    END
  END rw0_rd_out[43]
  PIN rw0_rd_out[44]
    DIRECTION OUTPUT ;
    USE SIGNAL ;
    SHAPE ABUTMENT ;
    PORT
      LAYER M3 ;
      RECT 23.751 0.000 23.769 0.054 ;
    END
  END rw0_rd_out[44]
  PIN rw0_rd_out[45]
    DIRECTION OUTPUT ;
    USE SIGNAL ;
    SHAPE ABUTMENT ;
    PORT
      LAYER M3 ;
      RECT 23.967 0.000 23.985 0.054 ;
    END
  END rw0_rd_out[45]
  PIN rw0_rd_out[46]
    DIRECTION OUTPUT ;
    USE SIGNAL ;
    SHAPE ABUTMENT ;
    PORT
      LAYER M3 ;
      RECT 24.183 0.000 24.201 0.054 ;
    END
  END rw0_rd_out[46]
  PIN rw0_rd_out[47]
    DIRECTION OUTPUT ;
    USE SIGNAL ;
    SHAPE ABUTMENT ;
    PORT
      LAYER M3 ;
      RECT 24.399 0.000 24.417 0.054 ;
    END
  END rw0_rd_out[47]
  PIN rw0_rd_out[48]
    DIRECTION OUTPUT ;
    USE SIGNAL ;
    SHAPE ABUTMENT ;
    PORT
      LAYER M3 ;
      RECT 24.615 0.000 24.633 0.054 ;
    END
  END rw0_rd_out[48]
  PIN rw0_rd_out[49]
    DIRECTION OUTPUT ;
    USE SIGNAL ;
    SHAPE ABUTMENT ;
    PORT
      LAYER M3 ;
      RECT 24.831 0.000 24.849 0.054 ;
    END
  END rw0_rd_out[49]
  PIN rw0_rd_out[50]
    DIRECTION OUTPUT ;
    USE SIGNAL ;
    SHAPE ABUTMENT ;
    PORT
      LAYER M3 ;
      RECT 25.047 0.000 25.065 0.054 ;
    END
  END rw0_rd_out[50]
  PIN rw0_rd_out[51]
    DIRECTION OUTPUT ;
    USE SIGNAL ;
    SHAPE ABUTMENT ;
    PORT
      LAYER M3 ;
      RECT 25.263 0.000 25.281 0.054 ;
    END
  END rw0_rd_out[51]
  PIN rw0_rd_out[52]
    DIRECTION OUTPUT ;
    USE SIGNAL ;
    SHAPE ABUTMENT ;
    PORT
      LAYER M3 ;
      RECT 25.479 0.000 25.497 0.054 ;
    END
  END rw0_rd_out[52]
  PIN rw0_rd_out[53]
    DIRECTION OUTPUT ;
    USE SIGNAL ;
    SHAPE ABUTMENT ;
    PORT
      LAYER M3 ;
      RECT 25.695 0.000 25.713 0.054 ;
    END
  END rw0_rd_out[53]
  PIN rw0_rd_out[54]
    DIRECTION OUTPUT ;
    USE SIGNAL ;
    SHAPE ABUTMENT ;
    PORT
      LAYER M3 ;
      RECT 25.911 0.000 25.929 0.054 ;
    END
  END rw0_rd_out[54]
  PIN rw0_rd_out[55]
    DIRECTION OUTPUT ;
    USE SIGNAL ;
    SHAPE ABUTMENT ;
    PORT
      LAYER M3 ;
      RECT 26.127 0.000 26.145 0.054 ;
    END
  END rw0_rd_out[55]
  PIN rw0_rd_out[56]
    DIRECTION OUTPUT ;
    USE SIGNAL ;
    SHAPE ABUTMENT ;
    PORT
      LAYER M3 ;
      RECT 26.343 0.000 26.361 0.054 ;
    END
  END rw0_rd_out[56]
  PIN rw0_rd_out[57]
    DIRECTION OUTPUT ;
    USE SIGNAL ;
    SHAPE ABUTMENT ;
    PORT
      LAYER M3 ;
      RECT 26.559 0.000 26.577 0.054 ;
    END
  END rw0_rd_out[57]
  PIN rw0_rd_out[58]
    DIRECTION OUTPUT ;
    USE SIGNAL ;
    SHAPE ABUTMENT ;
    PORT
      LAYER M3 ;
      RECT 26.775 0.000 26.793 0.054 ;
    END
  END rw0_rd_out[58]
  PIN rw0_rd_out[59]
    DIRECTION OUTPUT ;
    USE SIGNAL ;
    SHAPE ABUTMENT ;
    PORT
      LAYER M3 ;
      RECT 26.991 0.000 27.009 0.054 ;
    END
  END rw0_rd_out[59]
  PIN rw0_rd_out[60]
    DIRECTION OUTPUT ;
    USE SIGNAL ;
    SHAPE ABUTMENT ;
    PORT
      LAYER M3 ;
      RECT 27.207 0.000 27.225 0.054 ;
    END
  END rw0_rd_out[60]
  PIN rw0_rd_out[61]
    DIRECTION OUTPUT ;
    USE SIGNAL ;
    SHAPE ABUTMENT ;
    PORT
      LAYER M3 ;
      RECT 27.423 0.000 27.441 0.054 ;
    END
  END rw0_rd_out[61]
  PIN rw0_rd_out[62]
    DIRECTION OUTPUT ;
    USE SIGNAL ;
    SHAPE ABUTMENT ;
    PORT
      LAYER M3 ;
      RECT 27.639 0.000 27.657 0.054 ;
    END
  END rw0_rd_out[62]
  PIN rw0_rd_out[63]
    DIRECTION OUTPUT ;
    USE SIGNAL ;
    SHAPE ABUTMENT ;
    PORT
      LAYER M3 ;
      RECT 27.855 0.000 27.873 0.054 ;
    END
  END rw0_rd_out[63]
  PIN rw0_rd_out[64]
    DIRECTION OUTPUT ;
    USE SIGNAL ;
    SHAPE ABUTMENT ;
    PORT
      LAYER M3 ;
      RECT 28.071 0.000 28.089 0.054 ;
    END
  END rw0_rd_out[64]
  PIN rw0_rd_out[65]
    DIRECTION OUTPUT ;
    USE SIGNAL ;
    SHAPE ABUTMENT ;
    PORT
      LAYER M3 ;
      RECT 0.207 105.884 0.225 105.938 ;
    END
  END rw0_rd_out[65]
  PIN rw0_rd_out[66]
    DIRECTION OUTPUT ;
    USE SIGNAL ;
    SHAPE ABUTMENT ;
    PORT
      LAYER M3 ;
      RECT 0.495 105.884 0.513 105.938 ;
    END
  END rw0_rd_out[66]
  PIN rw0_rd_out[67]
    DIRECTION OUTPUT ;
    USE SIGNAL ;
    SHAPE ABUTMENT ;
    PORT
      LAYER M3 ;
      RECT 0.783 105.884 0.801 105.938 ;
    END
  END rw0_rd_out[67]
  PIN rw0_rd_out[68]
    DIRECTION OUTPUT ;
    USE SIGNAL ;
    SHAPE ABUTMENT ;
    PORT
      LAYER M3 ;
      RECT 1.071 105.884 1.089 105.938 ;
    END
  END rw0_rd_out[68]
  PIN rw0_rd_out[69]
    DIRECTION OUTPUT ;
    USE SIGNAL ;
    SHAPE ABUTMENT ;
    PORT
      LAYER M3 ;
      RECT 1.359 105.884 1.377 105.938 ;
    END
  END rw0_rd_out[69]
  PIN rw0_rd_out[70]
    DIRECTION OUTPUT ;
    USE SIGNAL ;
    SHAPE ABUTMENT ;
    PORT
      LAYER M3 ;
      RECT 1.647 105.884 1.665 105.938 ;
    END
  END rw0_rd_out[70]
  PIN rw0_rd_out[71]
    DIRECTION OUTPUT ;
    USE SIGNAL ;
    SHAPE ABUTMENT ;
    PORT
      LAYER M3 ;
      RECT 1.935 105.884 1.953 105.938 ;
    END
  END rw0_rd_out[71]
  PIN rw0_rd_out[72]
    DIRECTION OUTPUT ;
    USE SIGNAL ;
    SHAPE ABUTMENT ;
    PORT
      LAYER M3 ;
      RECT 2.223 105.884 2.241 105.938 ;
    END
  END rw0_rd_out[72]
  PIN rw0_rd_out[73]
    DIRECTION OUTPUT ;
    USE SIGNAL ;
    SHAPE ABUTMENT ;
    PORT
      LAYER M3 ;
      RECT 2.511 105.884 2.529 105.938 ;
    END
  END rw0_rd_out[73]
  PIN rw0_rd_out[74]
    DIRECTION OUTPUT ;
    USE SIGNAL ;
    SHAPE ABUTMENT ;
    PORT
      LAYER M3 ;
      RECT 2.799 105.884 2.817 105.938 ;
    END
  END rw0_rd_out[74]
  PIN rw0_rd_out[75]
    DIRECTION OUTPUT ;
    USE SIGNAL ;
    SHAPE ABUTMENT ;
    PORT
      LAYER M3 ;
      RECT 3.087 105.884 3.105 105.938 ;
    END
  END rw0_rd_out[75]
  PIN rw0_rd_out[76]
    DIRECTION OUTPUT ;
    USE SIGNAL ;
    SHAPE ABUTMENT ;
    PORT
      LAYER M3 ;
      RECT 3.375 105.884 3.393 105.938 ;
    END
  END rw0_rd_out[76]
  PIN rw0_rd_out[77]
    DIRECTION OUTPUT ;
    USE SIGNAL ;
    SHAPE ABUTMENT ;
    PORT
      LAYER M3 ;
      RECT 3.663 105.884 3.681 105.938 ;
    END
  END rw0_rd_out[77]
  PIN rw0_rd_out[78]
    DIRECTION OUTPUT ;
    USE SIGNAL ;
    SHAPE ABUTMENT ;
    PORT
      LAYER M3 ;
      RECT 3.951 105.884 3.969 105.938 ;
    END
  END rw0_rd_out[78]
  PIN rw0_rd_out[79]
    DIRECTION OUTPUT ;
    USE SIGNAL ;
    SHAPE ABUTMENT ;
    PORT
      LAYER M3 ;
      RECT 4.239 105.884 4.257 105.938 ;
    END
  END rw0_rd_out[79]
  PIN rw0_rd_out[80]
    DIRECTION OUTPUT ;
    USE SIGNAL ;
    SHAPE ABUTMENT ;
    PORT
      LAYER M3 ;
      RECT 4.527 105.884 4.545 105.938 ;
    END
  END rw0_rd_out[80]
  PIN rw0_rd_out[81]
    DIRECTION OUTPUT ;
    USE SIGNAL ;
    SHAPE ABUTMENT ;
    PORT
      LAYER M3 ;
      RECT 4.815 105.884 4.833 105.938 ;
    END
  END rw0_rd_out[81]
  PIN rw0_rd_out[82]
    DIRECTION OUTPUT ;
    USE SIGNAL ;
    SHAPE ABUTMENT ;
    PORT
      LAYER M3 ;
      RECT 5.103 105.884 5.121 105.938 ;
    END
  END rw0_rd_out[82]
  PIN rw0_rd_out[83]
    DIRECTION OUTPUT ;
    USE SIGNAL ;
    SHAPE ABUTMENT ;
    PORT
      LAYER M3 ;
      RECT 5.391 105.884 5.409 105.938 ;
    END
  END rw0_rd_out[83]
  PIN rw0_rd_out[84]
    DIRECTION OUTPUT ;
    USE SIGNAL ;
    SHAPE ABUTMENT ;
    PORT
      LAYER M3 ;
      RECT 5.679 105.884 5.697 105.938 ;
    END
  END rw0_rd_out[84]
  PIN rw0_rd_out[85]
    DIRECTION OUTPUT ;
    USE SIGNAL ;
    SHAPE ABUTMENT ;
    PORT
      LAYER M3 ;
      RECT 5.967 105.884 5.985 105.938 ;
    END
  END rw0_rd_out[85]
  PIN rw0_rd_out[86]
    DIRECTION OUTPUT ;
    USE SIGNAL ;
    SHAPE ABUTMENT ;
    PORT
      LAYER M3 ;
      RECT 6.255 105.884 6.273 105.938 ;
    END
  END rw0_rd_out[86]
  PIN rw0_rd_out[87]
    DIRECTION OUTPUT ;
    USE SIGNAL ;
    SHAPE ABUTMENT ;
    PORT
      LAYER M3 ;
      RECT 6.543 105.884 6.561 105.938 ;
    END
  END rw0_rd_out[87]
  PIN rw0_rd_out[88]
    DIRECTION OUTPUT ;
    USE SIGNAL ;
    SHAPE ABUTMENT ;
    PORT
      LAYER M3 ;
      RECT 6.831 105.884 6.849 105.938 ;
    END
  END rw0_rd_out[88]
  PIN rw0_rd_out[89]
    DIRECTION OUTPUT ;
    USE SIGNAL ;
    SHAPE ABUTMENT ;
    PORT
      LAYER M3 ;
      RECT 7.119 105.884 7.137 105.938 ;
    END
  END rw0_rd_out[89]
  PIN rw0_rd_out[90]
    DIRECTION OUTPUT ;
    USE SIGNAL ;
    SHAPE ABUTMENT ;
    PORT
      LAYER M3 ;
      RECT 7.407 105.884 7.425 105.938 ;
    END
  END rw0_rd_out[90]
  PIN rw0_rd_out[91]
    DIRECTION OUTPUT ;
    USE SIGNAL ;
    SHAPE ABUTMENT ;
    PORT
      LAYER M3 ;
      RECT 7.695 105.884 7.713 105.938 ;
    END
  END rw0_rd_out[91]
  PIN rw0_rd_out[92]
    DIRECTION OUTPUT ;
    USE SIGNAL ;
    SHAPE ABUTMENT ;
    PORT
      LAYER M3 ;
      RECT 7.983 105.884 8.001 105.938 ;
    END
  END rw0_rd_out[92]
  PIN rw0_rd_out[93]
    DIRECTION OUTPUT ;
    USE SIGNAL ;
    SHAPE ABUTMENT ;
    PORT
      LAYER M3 ;
      RECT 8.271 105.884 8.289 105.938 ;
    END
  END rw0_rd_out[93]
  PIN rw0_rd_out[94]
    DIRECTION OUTPUT ;
    USE SIGNAL ;
    SHAPE ABUTMENT ;
    PORT
      LAYER M3 ;
      RECT 8.559 105.884 8.577 105.938 ;
    END
  END rw0_rd_out[94]
  PIN rw0_rd_out[95]
    DIRECTION OUTPUT ;
    USE SIGNAL ;
    SHAPE ABUTMENT ;
    PORT
      LAYER M3 ;
      RECT 8.847 105.884 8.865 105.938 ;
    END
  END rw0_rd_out[95]
  PIN rw0_rd_out[96]
    DIRECTION OUTPUT ;
    USE SIGNAL ;
    SHAPE ABUTMENT ;
    PORT
      LAYER M3 ;
      RECT 9.135 105.884 9.153 105.938 ;
    END
  END rw0_rd_out[96]
  PIN rw0_rd_out[97]
    DIRECTION OUTPUT ;
    USE SIGNAL ;
    SHAPE ABUTMENT ;
    PORT
      LAYER M3 ;
      RECT 9.423 105.884 9.441 105.938 ;
    END
  END rw0_rd_out[97]
  PIN rw0_rd_out[98]
    DIRECTION OUTPUT ;
    USE SIGNAL ;
    SHAPE ABUTMENT ;
    PORT
      LAYER M3 ;
      RECT 9.711 105.884 9.729 105.938 ;
    END
  END rw0_rd_out[98]
  PIN rw0_rd_out[99]
    DIRECTION OUTPUT ;
    USE SIGNAL ;
    SHAPE ABUTMENT ;
    PORT
      LAYER M3 ;
      RECT 9.999 105.884 10.017 105.938 ;
    END
  END rw0_rd_out[99]
  PIN rw0_rd_out[100]
    DIRECTION OUTPUT ;
    USE SIGNAL ;
    SHAPE ABUTMENT ;
    PORT
      LAYER M3 ;
      RECT 10.287 105.884 10.305 105.938 ;
    END
  END rw0_rd_out[100]
  PIN rw0_rd_out[101]
    DIRECTION OUTPUT ;
    USE SIGNAL ;
    SHAPE ABUTMENT ;
    PORT
      LAYER M3 ;
      RECT 10.575 105.884 10.593 105.938 ;
    END
  END rw0_rd_out[101]
  PIN rw0_rd_out[102]
    DIRECTION OUTPUT ;
    USE SIGNAL ;
    SHAPE ABUTMENT ;
    PORT
      LAYER M3 ;
      RECT 10.863 105.884 10.881 105.938 ;
    END
  END rw0_rd_out[102]
  PIN rw0_rd_out[103]
    DIRECTION OUTPUT ;
    USE SIGNAL ;
    SHAPE ABUTMENT ;
    PORT
      LAYER M3 ;
      RECT 11.151 105.884 11.169 105.938 ;
    END
  END rw0_rd_out[103]
  PIN rw0_rd_out[104]
    DIRECTION OUTPUT ;
    USE SIGNAL ;
    SHAPE ABUTMENT ;
    PORT
      LAYER M3 ;
      RECT 11.439 105.884 11.457 105.938 ;
    END
  END rw0_rd_out[104]
  PIN rw0_rd_out[105]
    DIRECTION OUTPUT ;
    USE SIGNAL ;
    SHAPE ABUTMENT ;
    PORT
      LAYER M3 ;
      RECT 11.727 105.884 11.745 105.938 ;
    END
  END rw0_rd_out[105]
  PIN rw0_rd_out[106]
    DIRECTION OUTPUT ;
    USE SIGNAL ;
    SHAPE ABUTMENT ;
    PORT
      LAYER M3 ;
      RECT 12.015 105.884 12.033 105.938 ;
    END
  END rw0_rd_out[106]
  PIN rw0_rd_out[107]
    DIRECTION OUTPUT ;
    USE SIGNAL ;
    SHAPE ABUTMENT ;
    PORT
      LAYER M3 ;
      RECT 12.303 105.884 12.321 105.938 ;
    END
  END rw0_rd_out[107]
  PIN rw0_rd_out[108]
    DIRECTION OUTPUT ;
    USE SIGNAL ;
    SHAPE ABUTMENT ;
    PORT
      LAYER M3 ;
      RECT 12.591 105.884 12.609 105.938 ;
    END
  END rw0_rd_out[108]
  PIN rw0_rd_out[109]
    DIRECTION OUTPUT ;
    USE SIGNAL ;
    SHAPE ABUTMENT ;
    PORT
      LAYER M3 ;
      RECT 12.879 105.884 12.897 105.938 ;
    END
  END rw0_rd_out[109]
  PIN rw0_rd_out[110]
    DIRECTION OUTPUT ;
    USE SIGNAL ;
    SHAPE ABUTMENT ;
    PORT
      LAYER M3 ;
      RECT 13.167 105.884 13.185 105.938 ;
    END
  END rw0_rd_out[110]
  PIN rw0_rd_out[111]
    DIRECTION OUTPUT ;
    USE SIGNAL ;
    SHAPE ABUTMENT ;
    PORT
      LAYER M3 ;
      RECT 13.455 105.884 13.473 105.938 ;
    END
  END rw0_rd_out[111]
  PIN rw0_rd_out[112]
    DIRECTION OUTPUT ;
    USE SIGNAL ;
    SHAPE ABUTMENT ;
    PORT
      LAYER M3 ;
      RECT 13.743 105.884 13.761 105.938 ;
    END
  END rw0_rd_out[112]
  PIN rw0_rd_out[113]
    DIRECTION OUTPUT ;
    USE SIGNAL ;
    SHAPE ABUTMENT ;
    PORT
      LAYER M3 ;
      RECT 14.031 105.884 14.049 105.938 ;
    END
  END rw0_rd_out[113]
  PIN rw0_rd_out[114]
    DIRECTION OUTPUT ;
    USE SIGNAL ;
    SHAPE ABUTMENT ;
    PORT
      LAYER M3 ;
      RECT 14.319 105.884 14.337 105.938 ;
    END
  END rw0_rd_out[114]
  PIN rw0_rd_out[115]
    DIRECTION OUTPUT ;
    USE SIGNAL ;
    SHAPE ABUTMENT ;
    PORT
      LAYER M3 ;
      RECT 14.607 105.884 14.625 105.938 ;
    END
  END rw0_rd_out[115]
  PIN rw0_rd_out[116]
    DIRECTION OUTPUT ;
    USE SIGNAL ;
    SHAPE ABUTMENT ;
    PORT
      LAYER M3 ;
      RECT 14.895 105.884 14.913 105.938 ;
    END
  END rw0_rd_out[116]
  PIN rw0_rd_out[117]
    DIRECTION OUTPUT ;
    USE SIGNAL ;
    SHAPE ABUTMENT ;
    PORT
      LAYER M3 ;
      RECT 15.183 105.884 15.201 105.938 ;
    END
  END rw0_rd_out[117]
  PIN rw0_rd_out[118]
    DIRECTION OUTPUT ;
    USE SIGNAL ;
    SHAPE ABUTMENT ;
    PORT
      LAYER M3 ;
      RECT 15.471 105.884 15.489 105.938 ;
    END
  END rw0_rd_out[118]
  PIN rw0_rd_out[119]
    DIRECTION OUTPUT ;
    USE SIGNAL ;
    SHAPE ABUTMENT ;
    PORT
      LAYER M3 ;
      RECT 15.759 105.884 15.777 105.938 ;
    END
  END rw0_rd_out[119]
  PIN rw0_rd_out[120]
    DIRECTION OUTPUT ;
    USE SIGNAL ;
    SHAPE ABUTMENT ;
    PORT
      LAYER M3 ;
      RECT 16.047 105.884 16.065 105.938 ;
    END
  END rw0_rd_out[120]
  PIN rw0_rd_out[121]
    DIRECTION OUTPUT ;
    USE SIGNAL ;
    SHAPE ABUTMENT ;
    PORT
      LAYER M3 ;
      RECT 16.335 105.884 16.353 105.938 ;
    END
  END rw0_rd_out[121]
  PIN rw0_rd_out[122]
    DIRECTION OUTPUT ;
    USE SIGNAL ;
    SHAPE ABUTMENT ;
    PORT
      LAYER M3 ;
      RECT 16.623 105.884 16.641 105.938 ;
    END
  END rw0_rd_out[122]
  PIN rw0_rd_out[123]
    DIRECTION OUTPUT ;
    USE SIGNAL ;
    SHAPE ABUTMENT ;
    PORT
      LAYER M3 ;
      RECT 16.911 105.884 16.929 105.938 ;
    END
  END rw0_rd_out[123]
  PIN rw0_rd_out[124]
    DIRECTION OUTPUT ;
    USE SIGNAL ;
    SHAPE ABUTMENT ;
    PORT
      LAYER M3 ;
      RECT 17.199 105.884 17.217 105.938 ;
    END
  END rw0_rd_out[124]
  PIN rw0_rd_out[125]
    DIRECTION OUTPUT ;
    USE SIGNAL ;
    SHAPE ABUTMENT ;
    PORT
      LAYER M3 ;
      RECT 17.487 105.884 17.505 105.938 ;
    END
  END rw0_rd_out[125]
  PIN rw0_rd_out[126]
    DIRECTION OUTPUT ;
    USE SIGNAL ;
    SHAPE ABUTMENT ;
    PORT
      LAYER M3 ;
      RECT 17.775 105.884 17.793 105.938 ;
    END
  END rw0_rd_out[126]
  PIN rw0_rd_out[127]
    DIRECTION OUTPUT ;
    USE SIGNAL ;
    SHAPE ABUTMENT ;
    PORT
      LAYER M3 ;
      RECT 18.063 105.884 18.081 105.938 ;
    END
  END rw0_rd_out[127]
  PIN rw0_rd_out[128]
    DIRECTION OUTPUT ;
    USE SIGNAL ;
    SHAPE ABUTMENT ;
    PORT
      LAYER M3 ;
      RECT 18.351 105.884 18.369 105.938 ;
    END
  END rw0_rd_out[128]
  PIN rw0_rd_out[129]
    DIRECTION OUTPUT ;
    USE SIGNAL ;
    SHAPE ABUTMENT ;
    PORT
      LAYER M3 ;
      RECT 18.639 105.884 18.657 105.938 ;
    END
  END rw0_rd_out[129]
  PIN r0_rd_out[0]
    DIRECTION OUTPUT ;
    USE SIGNAL ;
    SHAPE ABUTMENT ;
    PORT
      LAYER M3 ;
      RECT 28.287 0.000 28.305 0.054 ;
    END
  END r0_rd_out[0]
  PIN r0_rd_out[1]
    DIRECTION OUTPUT ;
    USE SIGNAL ;
    SHAPE ABUTMENT ;
    PORT
      LAYER M3 ;
      RECT 28.503 0.000 28.521 0.054 ;
    END
  END r0_rd_out[1]
  PIN r0_rd_out[2]
    DIRECTION OUTPUT ;
    USE SIGNAL ;
    SHAPE ABUTMENT ;
    PORT
      LAYER M3 ;
      RECT 28.719 0.000 28.737 0.054 ;
    END
  END r0_rd_out[2]
  PIN r0_rd_out[3]
    DIRECTION OUTPUT ;
    USE SIGNAL ;
    SHAPE ABUTMENT ;
    PORT
      LAYER M3 ;
      RECT 28.935 0.000 28.953 0.054 ;
    END
  END r0_rd_out[3]
  PIN r0_rd_out[4]
    DIRECTION OUTPUT ;
    USE SIGNAL ;
    SHAPE ABUTMENT ;
    PORT
      LAYER M3 ;
      RECT 29.151 0.000 29.169 0.054 ;
    END
  END r0_rd_out[4]
  PIN r0_rd_out[5]
    DIRECTION OUTPUT ;
    USE SIGNAL ;
    SHAPE ABUTMENT ;
    PORT
      LAYER M3 ;
      RECT 29.367 0.000 29.385 0.054 ;
    END
  END r0_rd_out[5]
  PIN r0_rd_out[6]
    DIRECTION OUTPUT ;
    USE SIGNAL ;
    SHAPE ABUTMENT ;
    PORT
      LAYER M3 ;
      RECT 29.583 0.000 29.601 0.054 ;
    END
  END r0_rd_out[6]
  PIN r0_rd_out[7]
    DIRECTION OUTPUT ;
    USE SIGNAL ;
    SHAPE ABUTMENT ;
    PORT
      LAYER M3 ;
      RECT 29.799 0.000 29.817 0.054 ;
    END
  END r0_rd_out[7]
  PIN r0_rd_out[8]
    DIRECTION OUTPUT ;
    USE SIGNAL ;
    SHAPE ABUTMENT ;
    PORT
      LAYER M3 ;
      RECT 30.015 0.000 30.033 0.054 ;
    END
  END r0_rd_out[8]
  PIN r0_rd_out[9]
    DIRECTION OUTPUT ;
    USE SIGNAL ;
    SHAPE ABUTMENT ;
    PORT
      LAYER M3 ;
      RECT 30.231 0.000 30.249 0.054 ;
    END
  END r0_rd_out[9]
  PIN r0_rd_out[10]
    DIRECTION OUTPUT ;
    USE SIGNAL ;
    SHAPE ABUTMENT ;
    PORT
      LAYER M3 ;
      RECT 30.447 0.000 30.465 0.054 ;
    END
  END r0_rd_out[10]
  PIN r0_rd_out[11]
    DIRECTION OUTPUT ;
    USE SIGNAL ;
    SHAPE ABUTMENT ;
    PORT
      LAYER M3 ;
      RECT 30.663 0.000 30.681 0.054 ;
    END
  END r0_rd_out[11]
  PIN r0_rd_out[12]
    DIRECTION OUTPUT ;
    USE SIGNAL ;
    SHAPE ABUTMENT ;
    PORT
      LAYER M3 ;
      RECT 30.879 0.000 30.897 0.054 ;
    END
  END r0_rd_out[12]
  PIN r0_rd_out[13]
    DIRECTION OUTPUT ;
    USE SIGNAL ;
    SHAPE ABUTMENT ;
    PORT
      LAYER M3 ;
      RECT 31.095 0.000 31.113 0.054 ;
    END
  END r0_rd_out[13]
  PIN r0_rd_out[14]
    DIRECTION OUTPUT ;
    USE SIGNAL ;
    SHAPE ABUTMENT ;
    PORT
      LAYER M3 ;
      RECT 31.311 0.000 31.329 0.054 ;
    END
  END r0_rd_out[14]
  PIN r0_rd_out[15]
    DIRECTION OUTPUT ;
    USE SIGNAL ;
    SHAPE ABUTMENT ;
    PORT
      LAYER M3 ;
      RECT 31.527 0.000 31.545 0.054 ;
    END
  END r0_rd_out[15]
  PIN r0_rd_out[16]
    DIRECTION OUTPUT ;
    USE SIGNAL ;
    SHAPE ABUTMENT ;
    PORT
      LAYER M3 ;
      RECT 31.743 0.000 31.761 0.054 ;
    END
  END r0_rd_out[16]
  PIN r0_rd_out[17]
    DIRECTION OUTPUT ;
    USE SIGNAL ;
    SHAPE ABUTMENT ;
    PORT
      LAYER M3 ;
      RECT 31.959 0.000 31.977 0.054 ;
    END
  END r0_rd_out[17]
  PIN r0_rd_out[18]
    DIRECTION OUTPUT ;
    USE SIGNAL ;
    SHAPE ABUTMENT ;
    PORT
      LAYER M3 ;
      RECT 32.175 0.000 32.193 0.054 ;
    END
  END r0_rd_out[18]
  PIN r0_rd_out[19]
    DIRECTION OUTPUT ;
    USE SIGNAL ;
    SHAPE ABUTMENT ;
    PORT
      LAYER M3 ;
      RECT 32.391 0.000 32.409 0.054 ;
    END
  END r0_rd_out[19]
  PIN r0_rd_out[20]
    DIRECTION OUTPUT ;
    USE SIGNAL ;
    SHAPE ABUTMENT ;
    PORT
      LAYER M3 ;
      RECT 32.607 0.000 32.625 0.054 ;
    END
  END r0_rd_out[20]
  PIN r0_rd_out[21]
    DIRECTION OUTPUT ;
    USE SIGNAL ;
    SHAPE ABUTMENT ;
    PORT
      LAYER M3 ;
      RECT 32.823 0.000 32.841 0.054 ;
    END
  END r0_rd_out[21]
  PIN r0_rd_out[22]
    DIRECTION OUTPUT ;
    USE SIGNAL ;
    SHAPE ABUTMENT ;
    PORT
      LAYER M3 ;
      RECT 33.039 0.000 33.057 0.054 ;
    END
  END r0_rd_out[22]
  PIN r0_rd_out[23]
    DIRECTION OUTPUT ;
    USE SIGNAL ;
    SHAPE ABUTMENT ;
    PORT
      LAYER M3 ;
      RECT 33.255 0.000 33.273 0.054 ;
    END
  END r0_rd_out[23]
  PIN r0_rd_out[24]
    DIRECTION OUTPUT ;
    USE SIGNAL ;
    SHAPE ABUTMENT ;
    PORT
      LAYER M3 ;
      RECT 33.471 0.000 33.489 0.054 ;
    END
  END r0_rd_out[24]
  PIN r0_rd_out[25]
    DIRECTION OUTPUT ;
    USE SIGNAL ;
    SHAPE ABUTMENT ;
    PORT
      LAYER M3 ;
      RECT 33.687 0.000 33.705 0.054 ;
    END
  END r0_rd_out[25]
  PIN r0_rd_out[26]
    DIRECTION OUTPUT ;
    USE SIGNAL ;
    SHAPE ABUTMENT ;
    PORT
      LAYER M3 ;
      RECT 33.903 0.000 33.921 0.054 ;
    END
  END r0_rd_out[26]
  PIN r0_rd_out[27]
    DIRECTION OUTPUT ;
    USE SIGNAL ;
    SHAPE ABUTMENT ;
    PORT
      LAYER M3 ;
      RECT 34.119 0.000 34.137 0.054 ;
    END
  END r0_rd_out[27]
  PIN r0_rd_out[28]
    DIRECTION OUTPUT ;
    USE SIGNAL ;
    SHAPE ABUTMENT ;
    PORT
      LAYER M3 ;
      RECT 34.335 0.000 34.353 0.054 ;
    END
  END r0_rd_out[28]
  PIN r0_rd_out[29]
    DIRECTION OUTPUT ;
    USE SIGNAL ;
    SHAPE ABUTMENT ;
    PORT
      LAYER M3 ;
      RECT 34.551 0.000 34.569 0.054 ;
    END
  END r0_rd_out[29]
  PIN r0_rd_out[30]
    DIRECTION OUTPUT ;
    USE SIGNAL ;
    SHAPE ABUTMENT ;
    PORT
      LAYER M3 ;
      RECT 34.767 0.000 34.785 0.054 ;
    END
  END r0_rd_out[30]
  PIN r0_rd_out[31]
    DIRECTION OUTPUT ;
    USE SIGNAL ;
    SHAPE ABUTMENT ;
    PORT
      LAYER M3 ;
      RECT 34.983 0.000 35.001 0.054 ;
    END
  END r0_rd_out[31]
  PIN r0_rd_out[32]
    DIRECTION OUTPUT ;
    USE SIGNAL ;
    SHAPE ABUTMENT ;
    PORT
      LAYER M3 ;
      RECT 35.199 0.000 35.217 0.054 ;
    END
  END r0_rd_out[32]
  PIN r0_rd_out[33]
    DIRECTION OUTPUT ;
    USE SIGNAL ;
    SHAPE ABUTMENT ;
    PORT
      LAYER M3 ;
      RECT 35.415 0.000 35.433 0.054 ;
    END
  END r0_rd_out[33]
  PIN r0_rd_out[34]
    DIRECTION OUTPUT ;
    USE SIGNAL ;
    SHAPE ABUTMENT ;
    PORT
      LAYER M3 ;
      RECT 35.631 0.000 35.649 0.054 ;
    END
  END r0_rd_out[34]
  PIN r0_rd_out[35]
    DIRECTION OUTPUT ;
    USE SIGNAL ;
    SHAPE ABUTMENT ;
    PORT
      LAYER M3 ;
      RECT 35.847 0.000 35.865 0.054 ;
    END
  END r0_rd_out[35]
  PIN r0_rd_out[36]
    DIRECTION OUTPUT ;
    USE SIGNAL ;
    SHAPE ABUTMENT ;
    PORT
      LAYER M3 ;
      RECT 36.063 0.000 36.081 0.054 ;
    END
  END r0_rd_out[36]
  PIN r0_rd_out[37]
    DIRECTION OUTPUT ;
    USE SIGNAL ;
    SHAPE ABUTMENT ;
    PORT
      LAYER M3 ;
      RECT 36.279 0.000 36.297 0.054 ;
    END
  END r0_rd_out[37]
  PIN r0_rd_out[38]
    DIRECTION OUTPUT ;
    USE SIGNAL ;
    SHAPE ABUTMENT ;
    PORT
      LAYER M3 ;
      RECT 36.495 0.000 36.513 0.054 ;
    END
  END r0_rd_out[38]
  PIN r0_rd_out[39]
    DIRECTION OUTPUT ;
    USE SIGNAL ;
    SHAPE ABUTMENT ;
    PORT
      LAYER M3 ;
      RECT 36.711 0.000 36.729 0.054 ;
    END
  END r0_rd_out[39]
  PIN r0_rd_out[40]
    DIRECTION OUTPUT ;
    USE SIGNAL ;
    SHAPE ABUTMENT ;
    PORT
      LAYER M3 ;
      RECT 36.927 0.000 36.945 0.054 ;
    END
  END r0_rd_out[40]
  PIN r0_rd_out[41]
    DIRECTION OUTPUT ;
    USE SIGNAL ;
    SHAPE ABUTMENT ;
    PORT
      LAYER M3 ;
      RECT 37.143 0.000 37.161 0.054 ;
    END
  END r0_rd_out[41]
  PIN r0_rd_out[42]
    DIRECTION OUTPUT ;
    USE SIGNAL ;
    SHAPE ABUTMENT ;
    PORT
      LAYER M3 ;
      RECT 37.359 0.000 37.377 0.054 ;
    END
  END r0_rd_out[42]
  PIN r0_rd_out[43]
    DIRECTION OUTPUT ;
    USE SIGNAL ;
    SHAPE ABUTMENT ;
    PORT
      LAYER M3 ;
      RECT 37.575 0.000 37.593 0.054 ;
    END
  END r0_rd_out[43]
  PIN r0_rd_out[44]
    DIRECTION OUTPUT ;
    USE SIGNAL ;
    SHAPE ABUTMENT ;
    PORT
      LAYER M3 ;
      RECT 37.791 0.000 37.809 0.054 ;
    END
  END r0_rd_out[44]
  PIN r0_rd_out[45]
    DIRECTION OUTPUT ;
    USE SIGNAL ;
    SHAPE ABUTMENT ;
    PORT
      LAYER M3 ;
      RECT 38.007 0.000 38.025 0.054 ;
    END
  END r0_rd_out[45]
  PIN r0_rd_out[46]
    DIRECTION OUTPUT ;
    USE SIGNAL ;
    SHAPE ABUTMENT ;
    PORT
      LAYER M3 ;
      RECT 38.223 0.000 38.241 0.054 ;
    END
  END r0_rd_out[46]
  PIN r0_rd_out[47]
    DIRECTION OUTPUT ;
    USE SIGNAL ;
    SHAPE ABUTMENT ;
    PORT
      LAYER M3 ;
      RECT 38.439 0.000 38.457 0.054 ;
    END
  END r0_rd_out[47]
  PIN r0_rd_out[48]
    DIRECTION OUTPUT ;
    USE SIGNAL ;
    SHAPE ABUTMENT ;
    PORT
      LAYER M3 ;
      RECT 38.655 0.000 38.673 0.054 ;
    END
  END r0_rd_out[48]
  PIN r0_rd_out[49]
    DIRECTION OUTPUT ;
    USE SIGNAL ;
    SHAPE ABUTMENT ;
    PORT
      LAYER M3 ;
      RECT 38.871 0.000 38.889 0.054 ;
    END
  END r0_rd_out[49]
  PIN r0_rd_out[50]
    DIRECTION OUTPUT ;
    USE SIGNAL ;
    SHAPE ABUTMENT ;
    PORT
      LAYER M3 ;
      RECT 39.087 0.000 39.105 0.054 ;
    END
  END r0_rd_out[50]
  PIN r0_rd_out[51]
    DIRECTION OUTPUT ;
    USE SIGNAL ;
    SHAPE ABUTMENT ;
    PORT
      LAYER M3 ;
      RECT 39.303 0.000 39.321 0.054 ;
    END
  END r0_rd_out[51]
  PIN r0_rd_out[52]
    DIRECTION OUTPUT ;
    USE SIGNAL ;
    SHAPE ABUTMENT ;
    PORT
      LAYER M3 ;
      RECT 39.519 0.000 39.537 0.054 ;
    END
  END r0_rd_out[52]
  PIN r0_rd_out[53]
    DIRECTION OUTPUT ;
    USE SIGNAL ;
    SHAPE ABUTMENT ;
    PORT
      LAYER M3 ;
      RECT 39.735 0.000 39.753 0.054 ;
    END
  END r0_rd_out[53]
  PIN r0_rd_out[54]
    DIRECTION OUTPUT ;
    USE SIGNAL ;
    SHAPE ABUTMENT ;
    PORT
      LAYER M3 ;
      RECT 39.951 0.000 39.969 0.054 ;
    END
  END r0_rd_out[54]
  PIN r0_rd_out[55]
    DIRECTION OUTPUT ;
    USE SIGNAL ;
    SHAPE ABUTMENT ;
    PORT
      LAYER M3 ;
      RECT 40.167 0.000 40.185 0.054 ;
    END
  END r0_rd_out[55]
  PIN r0_rd_out[56]
    DIRECTION OUTPUT ;
    USE SIGNAL ;
    SHAPE ABUTMENT ;
    PORT
      LAYER M3 ;
      RECT 40.383 0.000 40.401 0.054 ;
    END
  END r0_rd_out[56]
  PIN r0_rd_out[57]
    DIRECTION OUTPUT ;
    USE SIGNAL ;
    SHAPE ABUTMENT ;
    PORT
      LAYER M3 ;
      RECT 40.599 0.000 40.617 0.054 ;
    END
  END r0_rd_out[57]
  PIN r0_rd_out[58]
    DIRECTION OUTPUT ;
    USE SIGNAL ;
    SHAPE ABUTMENT ;
    PORT
      LAYER M3 ;
      RECT 40.815 0.000 40.833 0.054 ;
    END
  END r0_rd_out[58]
  PIN r0_rd_out[59]
    DIRECTION OUTPUT ;
    USE SIGNAL ;
    SHAPE ABUTMENT ;
    PORT
      LAYER M3 ;
      RECT 41.031 0.000 41.049 0.054 ;
    END
  END r0_rd_out[59]
  PIN r0_rd_out[60]
    DIRECTION OUTPUT ;
    USE SIGNAL ;
    SHAPE ABUTMENT ;
    PORT
      LAYER M3 ;
      RECT 41.247 0.000 41.265 0.054 ;
    END
  END r0_rd_out[60]
  PIN r0_rd_out[61]
    DIRECTION OUTPUT ;
    USE SIGNAL ;
    SHAPE ABUTMENT ;
    PORT
      LAYER M3 ;
      RECT 41.463 0.000 41.481 0.054 ;
    END
  END r0_rd_out[61]
  PIN r0_rd_out[62]
    DIRECTION OUTPUT ;
    USE SIGNAL ;
    SHAPE ABUTMENT ;
    PORT
      LAYER M3 ;
      RECT 41.679 0.000 41.697 0.054 ;
    END
  END r0_rd_out[62]
  PIN r0_rd_out[63]
    DIRECTION OUTPUT ;
    USE SIGNAL ;
    SHAPE ABUTMENT ;
    PORT
      LAYER M3 ;
      RECT 41.895 0.000 41.913 0.054 ;
    END
  END r0_rd_out[63]
  PIN r0_rd_out[64]
    DIRECTION OUTPUT ;
    USE SIGNAL ;
    SHAPE ABUTMENT ;
    PORT
      LAYER M3 ;
      RECT 42.111 0.000 42.129 0.054 ;
    END
  END r0_rd_out[64]
  PIN r0_rd_out[65]
    DIRECTION OUTPUT ;
    USE SIGNAL ;
    SHAPE ABUTMENT ;
    PORT
      LAYER M3 ;
      RECT 18.927 105.884 18.945 105.938 ;
    END
  END r0_rd_out[65]
  PIN r0_rd_out[66]
    DIRECTION OUTPUT ;
    USE SIGNAL ;
    SHAPE ABUTMENT ;
    PORT
      LAYER M3 ;
      RECT 19.215 105.884 19.233 105.938 ;
    END
  END r0_rd_out[66]
  PIN r0_rd_out[67]
    DIRECTION OUTPUT ;
    USE SIGNAL ;
    SHAPE ABUTMENT ;
    PORT
      LAYER M3 ;
      RECT 19.503 105.884 19.521 105.938 ;
    END
  END r0_rd_out[67]
  PIN r0_rd_out[68]
    DIRECTION OUTPUT ;
    USE SIGNAL ;
    SHAPE ABUTMENT ;
    PORT
      LAYER M3 ;
      RECT 19.791 105.884 19.809 105.938 ;
    END
  END r0_rd_out[68]
  PIN r0_rd_out[69]
    DIRECTION OUTPUT ;
    USE SIGNAL ;
    SHAPE ABUTMENT ;
    PORT
      LAYER M3 ;
      RECT 20.079 105.884 20.097 105.938 ;
    END
  END r0_rd_out[69]
  PIN r0_rd_out[70]
    DIRECTION OUTPUT ;
    USE SIGNAL ;
    SHAPE ABUTMENT ;
    PORT
      LAYER M3 ;
      RECT 20.367 105.884 20.385 105.938 ;
    END
  END r0_rd_out[70]
  PIN r0_rd_out[71]
    DIRECTION OUTPUT ;
    USE SIGNAL ;
    SHAPE ABUTMENT ;
    PORT
      LAYER M3 ;
      RECT 20.655 105.884 20.673 105.938 ;
    END
  END r0_rd_out[71]
  PIN r0_rd_out[72]
    DIRECTION OUTPUT ;
    USE SIGNAL ;
    SHAPE ABUTMENT ;
    PORT
      LAYER M3 ;
      RECT 20.943 105.884 20.961 105.938 ;
    END
  END r0_rd_out[72]
  PIN r0_rd_out[73]
    DIRECTION OUTPUT ;
    USE SIGNAL ;
    SHAPE ABUTMENT ;
    PORT
      LAYER M3 ;
      RECT 21.231 105.884 21.249 105.938 ;
    END
  END r0_rd_out[73]
  PIN r0_rd_out[74]
    DIRECTION OUTPUT ;
    USE SIGNAL ;
    SHAPE ABUTMENT ;
    PORT
      LAYER M3 ;
      RECT 21.519 105.884 21.537 105.938 ;
    END
  END r0_rd_out[74]
  PIN r0_rd_out[75]
    DIRECTION OUTPUT ;
    USE SIGNAL ;
    SHAPE ABUTMENT ;
    PORT
      LAYER M3 ;
      RECT 21.807 105.884 21.825 105.938 ;
    END
  END r0_rd_out[75]
  PIN r0_rd_out[76]
    DIRECTION OUTPUT ;
    USE SIGNAL ;
    SHAPE ABUTMENT ;
    PORT
      LAYER M3 ;
      RECT 22.095 105.884 22.113 105.938 ;
    END
  END r0_rd_out[76]
  PIN r0_rd_out[77]
    DIRECTION OUTPUT ;
    USE SIGNAL ;
    SHAPE ABUTMENT ;
    PORT
      LAYER M3 ;
      RECT 22.383 105.884 22.401 105.938 ;
    END
  END r0_rd_out[77]
  PIN r0_rd_out[78]
    DIRECTION OUTPUT ;
    USE SIGNAL ;
    SHAPE ABUTMENT ;
    PORT
      LAYER M3 ;
      RECT 22.671 105.884 22.689 105.938 ;
    END
  END r0_rd_out[78]
  PIN r0_rd_out[79]
    DIRECTION OUTPUT ;
    USE SIGNAL ;
    SHAPE ABUTMENT ;
    PORT
      LAYER M3 ;
      RECT 22.959 105.884 22.977 105.938 ;
    END
  END r0_rd_out[79]
  PIN r0_rd_out[80]
    DIRECTION OUTPUT ;
    USE SIGNAL ;
    SHAPE ABUTMENT ;
    PORT
      LAYER M3 ;
      RECT 23.247 105.884 23.265 105.938 ;
    END
  END r0_rd_out[80]
  PIN r0_rd_out[81]
    DIRECTION OUTPUT ;
    USE SIGNAL ;
    SHAPE ABUTMENT ;
    PORT
      LAYER M3 ;
      RECT 23.535 105.884 23.553 105.938 ;
    END
  END r0_rd_out[81]
  PIN r0_rd_out[82]
    DIRECTION OUTPUT ;
    USE SIGNAL ;
    SHAPE ABUTMENT ;
    PORT
      LAYER M3 ;
      RECT 23.823 105.884 23.841 105.938 ;
    END
  END r0_rd_out[82]
  PIN r0_rd_out[83]
    DIRECTION OUTPUT ;
    USE SIGNAL ;
    SHAPE ABUTMENT ;
    PORT
      LAYER M3 ;
      RECT 24.111 105.884 24.129 105.938 ;
    END
  END r0_rd_out[83]
  PIN r0_rd_out[84]
    DIRECTION OUTPUT ;
    USE SIGNAL ;
    SHAPE ABUTMENT ;
    PORT
      LAYER M3 ;
      RECT 24.399 105.884 24.417 105.938 ;
    END
  END r0_rd_out[84]
  PIN r0_rd_out[85]
    DIRECTION OUTPUT ;
    USE SIGNAL ;
    SHAPE ABUTMENT ;
    PORT
      LAYER M3 ;
      RECT 24.687 105.884 24.705 105.938 ;
    END
  END r0_rd_out[85]
  PIN r0_rd_out[86]
    DIRECTION OUTPUT ;
    USE SIGNAL ;
    SHAPE ABUTMENT ;
    PORT
      LAYER M3 ;
      RECT 24.975 105.884 24.993 105.938 ;
    END
  END r0_rd_out[86]
  PIN r0_rd_out[87]
    DIRECTION OUTPUT ;
    USE SIGNAL ;
    SHAPE ABUTMENT ;
    PORT
      LAYER M3 ;
      RECT 25.263 105.884 25.281 105.938 ;
    END
  END r0_rd_out[87]
  PIN r0_rd_out[88]
    DIRECTION OUTPUT ;
    USE SIGNAL ;
    SHAPE ABUTMENT ;
    PORT
      LAYER M3 ;
      RECT 25.551 105.884 25.569 105.938 ;
    END
  END r0_rd_out[88]
  PIN r0_rd_out[89]
    DIRECTION OUTPUT ;
    USE SIGNAL ;
    SHAPE ABUTMENT ;
    PORT
      LAYER M3 ;
      RECT 25.839 105.884 25.857 105.938 ;
    END
  END r0_rd_out[89]
  PIN r0_rd_out[90]
    DIRECTION OUTPUT ;
    USE SIGNAL ;
    SHAPE ABUTMENT ;
    PORT
      LAYER M3 ;
      RECT 26.127 105.884 26.145 105.938 ;
    END
  END r0_rd_out[90]
  PIN r0_rd_out[91]
    DIRECTION OUTPUT ;
    USE SIGNAL ;
    SHAPE ABUTMENT ;
    PORT
      LAYER M3 ;
      RECT 26.415 105.884 26.433 105.938 ;
    END
  END r0_rd_out[91]
  PIN r0_rd_out[92]
    DIRECTION OUTPUT ;
    USE SIGNAL ;
    SHAPE ABUTMENT ;
    PORT
      LAYER M3 ;
      RECT 26.703 105.884 26.721 105.938 ;
    END
  END r0_rd_out[92]
  PIN r0_rd_out[93]
    DIRECTION OUTPUT ;
    USE SIGNAL ;
    SHAPE ABUTMENT ;
    PORT
      LAYER M3 ;
      RECT 26.991 105.884 27.009 105.938 ;
    END
  END r0_rd_out[93]
  PIN r0_rd_out[94]
    DIRECTION OUTPUT ;
    USE SIGNAL ;
    SHAPE ABUTMENT ;
    PORT
      LAYER M3 ;
      RECT 27.279 105.884 27.297 105.938 ;
    END
  END r0_rd_out[94]
  PIN r0_rd_out[95]
    DIRECTION OUTPUT ;
    USE SIGNAL ;
    SHAPE ABUTMENT ;
    PORT
      LAYER M3 ;
      RECT 27.567 105.884 27.585 105.938 ;
    END
  END r0_rd_out[95]
  PIN r0_rd_out[96]
    DIRECTION OUTPUT ;
    USE SIGNAL ;
    SHAPE ABUTMENT ;
    PORT
      LAYER M3 ;
      RECT 27.855 105.884 27.873 105.938 ;
    END
  END r0_rd_out[96]
  PIN r0_rd_out[97]
    DIRECTION OUTPUT ;
    USE SIGNAL ;
    SHAPE ABUTMENT ;
    PORT
      LAYER M3 ;
      RECT 28.143 105.884 28.161 105.938 ;
    END
  END r0_rd_out[97]
  PIN r0_rd_out[98]
    DIRECTION OUTPUT ;
    USE SIGNAL ;
    SHAPE ABUTMENT ;
    PORT
      LAYER M3 ;
      RECT 28.431 105.884 28.449 105.938 ;
    END
  END r0_rd_out[98]
  PIN r0_rd_out[99]
    DIRECTION OUTPUT ;
    USE SIGNAL ;
    SHAPE ABUTMENT ;
    PORT
      LAYER M3 ;
      RECT 28.719 105.884 28.737 105.938 ;
    END
  END r0_rd_out[99]
  PIN r0_rd_out[100]
    DIRECTION OUTPUT ;
    USE SIGNAL ;
    SHAPE ABUTMENT ;
    PORT
      LAYER M3 ;
      RECT 29.007 105.884 29.025 105.938 ;
    END
  END r0_rd_out[100]
  PIN r0_rd_out[101]
    DIRECTION OUTPUT ;
    USE SIGNAL ;
    SHAPE ABUTMENT ;
    PORT
      LAYER M3 ;
      RECT 29.295 105.884 29.313 105.938 ;
    END
  END r0_rd_out[101]
  PIN r0_rd_out[102]
    DIRECTION OUTPUT ;
    USE SIGNAL ;
    SHAPE ABUTMENT ;
    PORT
      LAYER M3 ;
      RECT 29.583 105.884 29.601 105.938 ;
    END
  END r0_rd_out[102]
  PIN r0_rd_out[103]
    DIRECTION OUTPUT ;
    USE SIGNAL ;
    SHAPE ABUTMENT ;
    PORT
      LAYER M3 ;
      RECT 29.871 105.884 29.889 105.938 ;
    END
  END r0_rd_out[103]
  PIN r0_rd_out[104]
    DIRECTION OUTPUT ;
    USE SIGNAL ;
    SHAPE ABUTMENT ;
    PORT
      LAYER M3 ;
      RECT 30.159 105.884 30.177 105.938 ;
    END
  END r0_rd_out[104]
  PIN r0_rd_out[105]
    DIRECTION OUTPUT ;
    USE SIGNAL ;
    SHAPE ABUTMENT ;
    PORT
      LAYER M3 ;
      RECT 30.447 105.884 30.465 105.938 ;
    END
  END r0_rd_out[105]
  PIN r0_rd_out[106]
    DIRECTION OUTPUT ;
    USE SIGNAL ;
    SHAPE ABUTMENT ;
    PORT
      LAYER M3 ;
      RECT 30.735 105.884 30.753 105.938 ;
    END
  END r0_rd_out[106]
  PIN r0_rd_out[107]
    DIRECTION OUTPUT ;
    USE SIGNAL ;
    SHAPE ABUTMENT ;
    PORT
      LAYER M3 ;
      RECT 31.023 105.884 31.041 105.938 ;
    END
  END r0_rd_out[107]
  PIN r0_rd_out[108]
    DIRECTION OUTPUT ;
    USE SIGNAL ;
    SHAPE ABUTMENT ;
    PORT
      LAYER M3 ;
      RECT 31.311 105.884 31.329 105.938 ;
    END
  END r0_rd_out[108]
  PIN r0_rd_out[109]
    DIRECTION OUTPUT ;
    USE SIGNAL ;
    SHAPE ABUTMENT ;
    PORT
      LAYER M3 ;
      RECT 31.599 105.884 31.617 105.938 ;
    END
  END r0_rd_out[109]
  PIN r0_rd_out[110]
    DIRECTION OUTPUT ;
    USE SIGNAL ;
    SHAPE ABUTMENT ;
    PORT
      LAYER M3 ;
      RECT 31.887 105.884 31.905 105.938 ;
    END
  END r0_rd_out[110]
  PIN r0_rd_out[111]
    DIRECTION OUTPUT ;
    USE SIGNAL ;
    SHAPE ABUTMENT ;
    PORT
      LAYER M3 ;
      RECT 32.175 105.884 32.193 105.938 ;
    END
  END r0_rd_out[111]
  PIN r0_rd_out[112]
    DIRECTION OUTPUT ;
    USE SIGNAL ;
    SHAPE ABUTMENT ;
    PORT
      LAYER M3 ;
      RECT 32.463 105.884 32.481 105.938 ;
    END
  END r0_rd_out[112]
  PIN r0_rd_out[113]
    DIRECTION OUTPUT ;
    USE SIGNAL ;
    SHAPE ABUTMENT ;
    PORT
      LAYER M3 ;
      RECT 32.751 105.884 32.769 105.938 ;
    END
  END r0_rd_out[113]
  PIN r0_rd_out[114]
    DIRECTION OUTPUT ;
    USE SIGNAL ;
    SHAPE ABUTMENT ;
    PORT
      LAYER M3 ;
      RECT 33.039 105.884 33.057 105.938 ;
    END
  END r0_rd_out[114]
  PIN r0_rd_out[115]
    DIRECTION OUTPUT ;
    USE SIGNAL ;
    SHAPE ABUTMENT ;
    PORT
      LAYER M3 ;
      RECT 33.327 105.884 33.345 105.938 ;
    END
  END r0_rd_out[115]
  PIN r0_rd_out[116]
    DIRECTION OUTPUT ;
    USE SIGNAL ;
    SHAPE ABUTMENT ;
    PORT
      LAYER M3 ;
      RECT 33.615 105.884 33.633 105.938 ;
    END
  END r0_rd_out[116]
  PIN r0_rd_out[117]
    DIRECTION OUTPUT ;
    USE SIGNAL ;
    SHAPE ABUTMENT ;
    PORT
      LAYER M3 ;
      RECT 33.903 105.884 33.921 105.938 ;
    END
  END r0_rd_out[117]
  PIN r0_rd_out[118]
    DIRECTION OUTPUT ;
    USE SIGNAL ;
    SHAPE ABUTMENT ;
    PORT
      LAYER M3 ;
      RECT 34.191 105.884 34.209 105.938 ;
    END
  END r0_rd_out[118]
  PIN r0_rd_out[119]
    DIRECTION OUTPUT ;
    USE SIGNAL ;
    SHAPE ABUTMENT ;
    PORT
      LAYER M3 ;
      RECT 34.479 105.884 34.497 105.938 ;
    END
  END r0_rd_out[119]
  PIN r0_rd_out[120]
    DIRECTION OUTPUT ;
    USE SIGNAL ;
    SHAPE ABUTMENT ;
    PORT
      LAYER M3 ;
      RECT 34.767 105.884 34.785 105.938 ;
    END
  END r0_rd_out[120]
  PIN r0_rd_out[121]
    DIRECTION OUTPUT ;
    USE SIGNAL ;
    SHAPE ABUTMENT ;
    PORT
      LAYER M3 ;
      RECT 35.055 105.884 35.073 105.938 ;
    END
  END r0_rd_out[121]
  PIN r0_rd_out[122]
    DIRECTION OUTPUT ;
    USE SIGNAL ;
    SHAPE ABUTMENT ;
    PORT
      LAYER M3 ;
      RECT 35.343 105.884 35.361 105.938 ;
    END
  END r0_rd_out[122]
  PIN r0_rd_out[123]
    DIRECTION OUTPUT ;
    USE SIGNAL ;
    SHAPE ABUTMENT ;
    PORT
      LAYER M3 ;
      RECT 35.631 105.884 35.649 105.938 ;
    END
  END r0_rd_out[123]
  PIN r0_rd_out[124]
    DIRECTION OUTPUT ;
    USE SIGNAL ;
    SHAPE ABUTMENT ;
    PORT
      LAYER M3 ;
      RECT 35.919 105.884 35.937 105.938 ;
    END
  END r0_rd_out[124]
  PIN r0_rd_out[125]
    DIRECTION OUTPUT ;
    USE SIGNAL ;
    SHAPE ABUTMENT ;
    PORT
      LAYER M3 ;
      RECT 36.207 105.884 36.225 105.938 ;
    END
  END r0_rd_out[125]
  PIN r0_rd_out[126]
    DIRECTION OUTPUT ;
    USE SIGNAL ;
    SHAPE ABUTMENT ;
    PORT
      LAYER M3 ;
      RECT 36.495 105.884 36.513 105.938 ;
    END
  END r0_rd_out[126]
  PIN r0_rd_out[127]
    DIRECTION OUTPUT ;
    USE SIGNAL ;
    SHAPE ABUTMENT ;
    PORT
      LAYER M3 ;
      RECT 36.783 105.884 36.801 105.938 ;
    END
  END r0_rd_out[127]
  PIN r0_rd_out[128]
    DIRECTION OUTPUT ;
    USE SIGNAL ;
    SHAPE ABUTMENT ;
    PORT
      LAYER M3 ;
      RECT 37.071 105.884 37.089 105.938 ;
    END
  END r0_rd_out[128]
  PIN r0_rd_out[129]
    DIRECTION OUTPUT ;
    USE SIGNAL ;
    SHAPE ABUTMENT ;
    PORT
      LAYER M3 ;
      RECT 37.359 105.884 37.377 105.938 ;
    END
  END r0_rd_out[129]
  PIN rw0_addr_in[0]
    DIRECTION INPUT ;
    USE SIGNAL ;
    SHAPE ABUTMENT ;
    PORT
      LAYER M4 ;
      RECT 0.000 82.644 0.072 82.668 ;
    END
  END rw0_addr_in[0]
  PIN rw0_addr_in[1]
    DIRECTION INPUT ;
    USE SIGNAL ;
    SHAPE ABUTMENT ;
    PORT
      LAYER M4 ;
      RECT 0.000 85.140 0.072 85.164 ;
    END
  END rw0_addr_in[1]
  PIN rw0_addr_in[2]
    DIRECTION INPUT ;
    USE SIGNAL ;
    SHAPE ABUTMENT ;
    PORT
      LAYER M4 ;
      RECT 0.000 87.636 0.072 87.660 ;
    END
  END rw0_addr_in[2]
  PIN rw0_addr_in[3]
    DIRECTION INPUT ;
    USE SIGNAL ;
    SHAPE ABUTMENT ;
    PORT
      LAYER M4 ;
      RECT 0.000 90.132 0.072 90.156 ;
    END
  END rw0_addr_in[3]
  PIN rw0_addr_in[4]
    DIRECTION INPUT ;
    USE SIGNAL ;
    SHAPE ABUTMENT ;
    PORT
      LAYER M4 ;
      RECT 0.000 92.628 0.072 92.652 ;
    END
  END rw0_addr_in[4]
  PIN rw0_addr_in[5]
    DIRECTION INPUT ;
    USE SIGNAL ;
    SHAPE ABUTMENT ;
    PORT
      LAYER M4 ;
      RECT 42.891 80.148 42.963 80.172 ;
    END
  END rw0_addr_in[5]
  PIN rw0_addr_in[6]
    DIRECTION INPUT ;
    USE SIGNAL ;
    SHAPE ABUTMENT ;
    PORT
      LAYER M4 ;
      RECT 42.891 82.644 42.963 82.668 ;
    END
  END rw0_addr_in[6]
  PIN rw0_addr_in[7]
    DIRECTION INPUT ;
    USE SIGNAL ;
    SHAPE ABUTMENT ;
    PORT
      LAYER M4 ;
      RECT 42.891 85.140 42.963 85.164 ;
    END
  END rw0_addr_in[7]
  PIN rw0_addr_in[8]
    DIRECTION INPUT ;
    USE SIGNAL ;
    SHAPE ABUTMENT ;
    PORT
      LAYER M4 ;
      RECT 42.891 87.636 42.963 87.660 ;
    END
  END rw0_addr_in[8]
  PIN r0_addr_in[0]
    DIRECTION INPUT ;
    USE SIGNAL ;
    SHAPE ABUTMENT ;
    PORT
      LAYER M4 ;
      RECT 0.000 95.124 0.072 95.148 ;
    END
  END r0_addr_in[0]
  PIN r0_addr_in[1]
    DIRECTION INPUT ;
    USE SIGNAL ;
    SHAPE ABUTMENT ;
    PORT
      LAYER M4 ;
      RECT 0.000 97.620 0.072 97.644 ;
    END
  END r0_addr_in[1]
  PIN r0_addr_in[2]
    DIRECTION INPUT ;
    USE SIGNAL ;
    SHAPE ABUTMENT ;
    PORT
      LAYER M4 ;
      RECT 0.000 100.116 0.072 100.140 ;
    END
  END r0_addr_in[2]
  PIN r0_addr_in[3]
    DIRECTION INPUT ;
    USE SIGNAL ;
    SHAPE ABUTMENT ;
    PORT
      LAYER M4 ;
      RECT 0.000 102.612 0.072 102.636 ;
    END
  END r0_addr_in[3]
  PIN r0_addr_in[4]
    DIRECTION INPUT ;
    USE SIGNAL ;
    SHAPE ABUTMENT ;
    PORT
      LAYER M4 ;
      RECT 0.000 105.108 0.072 105.132 ;
    END
  END r0_addr_in[4]
  PIN r0_addr_in[5]
    DIRECTION INPUT ;
    USE SIGNAL ;
    SHAPE ABUTMENT ;
    PORT
      LAYER M4 ;
      RECT 42.891 90.132 42.963 90.156 ;
    END
  END r0_addr_in[5]
  PIN r0_addr_in[6]
    DIRECTION INPUT ;
    USE SIGNAL ;
    SHAPE ABUTMENT ;
    PORT
      LAYER M4 ;
      RECT 42.891 92.628 42.963 92.652 ;
    END
  END r0_addr_in[6]
  PIN r0_addr_in[7]
    DIRECTION INPUT ;
    USE SIGNAL ;
    SHAPE ABUTMENT ;
    PORT
      LAYER M4 ;
      RECT 42.891 95.124 42.963 95.148 ;
    END
  END r0_addr_in[7]
  PIN r0_addr_in[8]
    DIRECTION INPUT ;
    USE SIGNAL ;
    SHAPE ABUTMENT ;
    PORT
      LAYER M4 ;
      RECT 42.891 97.620 42.963 97.644 ;
    END
  END r0_addr_in[8]
  PIN rw0_we_in
    DIRECTION INPUT ;
    USE SIGNAL ;
    SHAPE ABUTMENT ;
    PORT
      LAYER M3 ;
      RECT 37.647 105.884 37.665 105.938 ;
    END
  END rw0_we_in
  PIN rw0_ce_in
    DIRECTION INPUT ;
    USE SIGNAL ;
    SHAPE ABUTMENT ;
    PORT
      LAYER M3 ;
      RECT 37.935 105.884 37.953 105.938 ;
    END
  END rw0_ce_in
  PIN rw0_clk
    DIRECTION INPUT ;
    USE SIGNAL ;
    SHAPE ABUTMENT ;
    PORT
      LAYER M3 ;
      RECT 38.223 105.884 38.241 105.938 ;
    END
  END rw0_clk
  PIN r0_ce_in
    DIRECTION INPUT ;
    USE SIGNAL ;
    SHAPE ABUTMENT ;
    PORT
      LAYER M3 ;
      RECT 38.511 105.884 38.529 105.938 ;
    END
  END r0_ce_in
  PIN r0_clk
    DIRECTION INPUT ;
    USE SIGNAL ;
    SHAPE ABUTMENT ;
    PORT
      LAYER M3 ;
      RECT 38.799 105.884 38.817 105.938 ;
    END
  END r0_clk
  PIN VSS
    DIRECTION INOUT ;
    USE GROUND ;
    PORT
      LAYER M4 ;
      RECT 0.216 0.240 42.747 0.336 ;
      RECT 0.216 1.008 42.747 1.104 ;
      RECT 0.216 1.776 42.747 1.872 ;
      RECT 0.216 2.544 42.747 2.640 ;
      RECT 0.216 3.312 42.747 3.408 ;
      RECT 0.216 4.080 42.747 4.176 ;
      RECT 0.216 4.848 42.747 4.944 ;
      RECT 0.216 5.616 42.747 5.712 ;
      RECT 0.216 6.384 42.747 6.480 ;
      RECT 0.216 7.152 42.747 7.248 ;
      RECT 0.216 7.920 42.747 8.016 ;
      RECT 0.216 8.688 42.747 8.784 ;
      RECT 0.216 9.456 42.747 9.552 ;
      RECT 0.216 10.224 42.747 10.320 ;
      RECT 0.216 10.992 42.747 11.088 ;
      RECT 0.216 11.760 42.747 11.856 ;
      RECT 0.216 12.528 42.747 12.624 ;
      RECT 0.216 13.296 42.747 13.392 ;
      RECT 0.216 14.064 42.747 14.160 ;
      RECT 0.216 14.832 42.747 14.928 ;
      RECT 0.216 15.600 42.747 15.696 ;
      RECT 0.216 16.368 42.747 16.464 ;
      RECT 0.216 17.136 42.747 17.232 ;
      RECT 0.216 17.904 42.747 18.000 ;
      RECT 0.216 18.672 42.747 18.768 ;
      RECT 0.216 19.440 42.747 19.536 ;
      RECT 0.216 20.208 42.747 20.304 ;
      RECT 0.216 20.976 42.747 21.072 ;
      RECT 0.216 21.744 42.747 21.840 ;
      RECT 0.216 22.512 42.747 22.608 ;
      RECT 0.216 23.280 42.747 23.376 ;
      RECT 0.216 24.048 42.747 24.144 ;
      RECT 0.216 24.816 42.747 24.912 ;
      RECT 0.216 25.584 42.747 25.680 ;
      RECT 0.216 26.352 42.747 26.448 ;
      RECT 0.216 27.120 42.747 27.216 ;
      RECT 0.216 27.888 42.747 27.984 ;
      RECT 0.216 28.656 42.747 28.752 ;
      RECT 0.216 29.424 42.747 29.520 ;
      RECT 0.216 30.192 42.747 30.288 ;
      RECT 0.216 30.960 42.747 31.056 ;
      RECT 0.216 31.728 42.747 31.824 ;
      RECT 0.216 32.496 42.747 32.592 ;
      RECT 0.216 33.264 42.747 33.360 ;
      RECT 0.216 34.032 42.747 34.128 ;
      RECT 0.216 34.800 42.747 34.896 ;
      RECT 0.216 35.568 42.747 35.664 ;
      RECT 0.216 36.336 42.747 36.432 ;
      RECT 0.216 37.104 42.747 37.200 ;
      RECT 0.216 37.872 42.747 37.968 ;
      RECT 0.216 38.640 42.747 38.736 ;
      RECT 0.216 39.408 42.747 39.504 ;
      RECT 0.216 40.176 42.747 40.272 ;
      RECT 0.216 40.944 42.747 41.040 ;
      RECT 0.216 41.712 42.747 41.808 ;
      RECT 0.216 42.480 42.747 42.576 ;
      RECT 0.216 43.248 42.747 43.344 ;
      RECT 0.216 44.016 42.747 44.112 ;
      RECT 0.216 44.784 42.747 44.880 ;
      RECT 0.216 45.552 42.747 45.648 ;
      RECT 0.216 46.320 42.747 46.416 ;
      RECT 0.216 47.088 42.747 47.184 ;
      RECT 0.216 47.856 42.747 47.952 ;
      RECT 0.216 48.624 42.747 48.720 ;
      RECT 0.216 49.392 42.747 49.488 ;
      RECT 0.216 50.160 42.747 50.256 ;
      RECT 0.216 50.928 42.747 51.024 ;
      RECT 0.216 51.696 42.747 51.792 ;
      RECT 0.216 52.464 42.747 52.560 ;
      RECT 0.216 53.232 42.747 53.328 ;
      RECT 0.216 54.000 42.747 54.096 ;
      RECT 0.216 54.768 42.747 54.864 ;
      RECT 0.216 55.536 42.747 55.632 ;
      RECT 0.216 56.304 42.747 56.400 ;
      RECT 0.216 57.072 42.747 57.168 ;
      RECT 0.216 57.840 42.747 57.936 ;
      RECT 0.216 58.608 42.747 58.704 ;
      RECT 0.216 59.376 42.747 59.472 ;
      RECT 0.216 60.144 42.747 60.240 ;
      RECT 0.216 60.912 42.747 61.008 ;
      RECT 0.216 61.680 42.747 61.776 ;
      RECT 0.216 62.448 42.747 62.544 ;
      RECT 0.216 63.216 42.747 63.312 ;
      RECT 0.216 63.984 42.747 64.080 ;
      RECT 0.216 64.752 42.747 64.848 ;
      RECT 0.216 65.520 42.747 65.616 ;
      RECT 0.216 66.288 42.747 66.384 ;
      RECT 0.216 67.056 42.747 67.152 ;
      RECT 0.216 67.824 42.747 67.920 ;
      RECT 0.216 68.592 42.747 68.688 ;
      RECT 0.216 69.360 42.747 69.456 ;
      RECT 0.216 70.128 42.747 70.224 ;
      RECT 0.216 70.896 42.747 70.992 ;
      RECT 0.216 71.664 42.747 71.760 ;
      RECT 0.216 72.432 42.747 72.528 ;
      RECT 0.216 73.200 42.747 73.296 ;
      RECT 0.216 73.968 42.747 74.064 ;
      RECT 0.216 74.736 42.747 74.832 ;
      RECT 0.216 75.504 42.747 75.600 ;
      RECT 0.216 76.272 42.747 76.368 ;
      RECT 0.216 77.040 42.747 77.136 ;
      RECT 0.216 77.808 42.747 77.904 ;
      RECT 0.216 78.576 42.747 78.672 ;
      RECT 0.216 79.344 42.747 79.440 ;
      RECT 0.216 80.112 42.747 80.208 ;
      RECT 0.216 80.880 42.747 80.976 ;
      RECT 0.216 81.648 42.747 81.744 ;
      RECT 0.216 82.416 42.747 82.512 ;
      RECT 0.216 83.184 42.747 83.280 ;
      RECT 0.216 83.952 42.747 84.048 ;
      RECT 0.216 84.720 42.747 84.816 ;
      RECT 0.216 85.488 42.747 85.584 ;
      RECT 0.216 86.256 42.747 86.352 ;
      RECT 0.216 87.024 42.747 87.120 ;
      RECT 0.216 87.792 42.747 87.888 ;
      RECT 0.216 88.560 42.747 88.656 ;
      RECT 0.216 89.328 42.747 89.424 ;
      RECT 0.216 90.096 42.747 90.192 ;
      RECT 0.216 90.864 42.747 90.960 ;
      RECT 0.216 91.632 42.747 91.728 ;
      RECT 0.216 92.400 42.747 92.496 ;
      RECT 0.216 93.168 42.747 93.264 ;
      RECT 0.216 93.936 42.747 94.032 ;
      RECT 0.216 94.704 42.747 94.800 ;
      RECT 0.216 95.472 42.747 95.568 ;
      RECT 0.216 96.240 42.747 96.336 ;
      RECT 0.216 97.008 42.747 97.104 ;
      RECT 0.216 97.776 42.747 97.872 ;
      RECT 0.216 98.544 42.747 98.640 ;
      RECT 0.216 99.312 42.747 99.408 ;
      RECT 0.216 100.080 42.747 100.176 ;
      RECT 0.216 100.848 42.747 100.944 ;
      RECT 0.216 101.616 42.747 101.712 ;
      RECT 0.216 102.384 42.747 102.480 ;
      RECT 0.216 103.152 42.747 103.248 ;
      RECT 0.216 103.920 42.747 104.016 ;
      RECT 0.216 104.688 42.747 104.784 ;
      RECT 0.216 105.456 42.747 105.552 ;
    END
  END VSS
  PIN VDD
    DIRECTION INOUT ;
    USE POWER ;
    PORT
      LAYER M4 ;
      RECT 0.216 0.240 42.747 0.336 ;
      RECT 0.216 1.008 42.747 1.104 ;
      RECT 0.216 1.776 42.747 1.872 ;
      RECT 0.216 2.544 42.747 2.640 ;
      RECT 0.216 3.312 42.747 3.408 ;
      RECT 0.216 4.080 42.747 4.176 ;
      RECT 0.216 4.848 42.747 4.944 ;
      RECT 0.216 5.616 42.747 5.712 ;
      RECT 0.216 6.384 42.747 6.480 ;
      RECT 0.216 7.152 42.747 7.248 ;
      RECT 0.216 7.920 42.747 8.016 ;
      RECT 0.216 8.688 42.747 8.784 ;
      RECT 0.216 9.456 42.747 9.552 ;
      RECT 0.216 10.224 42.747 10.320 ;
      RECT 0.216 10.992 42.747 11.088 ;
      RECT 0.216 11.760 42.747 11.856 ;
      RECT 0.216 12.528 42.747 12.624 ;
      RECT 0.216 13.296 42.747 13.392 ;
      RECT 0.216 14.064 42.747 14.160 ;
      RECT 0.216 14.832 42.747 14.928 ;
      RECT 0.216 15.600 42.747 15.696 ;
      RECT 0.216 16.368 42.747 16.464 ;
      RECT 0.216 17.136 42.747 17.232 ;
      RECT 0.216 17.904 42.747 18.000 ;
      RECT 0.216 18.672 42.747 18.768 ;
      RECT 0.216 19.440 42.747 19.536 ;
      RECT 0.216 20.208 42.747 20.304 ;
      RECT 0.216 20.976 42.747 21.072 ;
      RECT 0.216 21.744 42.747 21.840 ;
      RECT 0.216 22.512 42.747 22.608 ;
      RECT 0.216 23.280 42.747 23.376 ;
      RECT 0.216 24.048 42.747 24.144 ;
      RECT 0.216 24.816 42.747 24.912 ;
      RECT 0.216 25.584 42.747 25.680 ;
      RECT 0.216 26.352 42.747 26.448 ;
      RECT 0.216 27.120 42.747 27.216 ;
      RECT 0.216 27.888 42.747 27.984 ;
      RECT 0.216 28.656 42.747 28.752 ;
      RECT 0.216 29.424 42.747 29.520 ;
      RECT 0.216 30.192 42.747 30.288 ;
      RECT 0.216 30.960 42.747 31.056 ;
      RECT 0.216 31.728 42.747 31.824 ;
      RECT 0.216 32.496 42.747 32.592 ;
      RECT 0.216 33.264 42.747 33.360 ;
      RECT 0.216 34.032 42.747 34.128 ;
      RECT 0.216 34.800 42.747 34.896 ;
      RECT 0.216 35.568 42.747 35.664 ;
      RECT 0.216 36.336 42.747 36.432 ;
      RECT 0.216 37.104 42.747 37.200 ;
      RECT 0.216 37.872 42.747 37.968 ;
      RECT 0.216 38.640 42.747 38.736 ;
      RECT 0.216 39.408 42.747 39.504 ;
      RECT 0.216 40.176 42.747 40.272 ;
      RECT 0.216 40.944 42.747 41.040 ;
      RECT 0.216 41.712 42.747 41.808 ;
      RECT 0.216 42.480 42.747 42.576 ;
      RECT 0.216 43.248 42.747 43.344 ;
      RECT 0.216 44.016 42.747 44.112 ;
      RECT 0.216 44.784 42.747 44.880 ;
      RECT 0.216 45.552 42.747 45.648 ;
      RECT 0.216 46.320 42.747 46.416 ;
      RECT 0.216 47.088 42.747 47.184 ;
      RECT 0.216 47.856 42.747 47.952 ;
      RECT 0.216 48.624 42.747 48.720 ;
      RECT 0.216 49.392 42.747 49.488 ;
      RECT 0.216 50.160 42.747 50.256 ;
      RECT 0.216 50.928 42.747 51.024 ;
      RECT 0.216 51.696 42.747 51.792 ;
      RECT 0.216 52.464 42.747 52.560 ;
      RECT 0.216 53.232 42.747 53.328 ;
      RECT 0.216 54.000 42.747 54.096 ;
      RECT 0.216 54.768 42.747 54.864 ;
      RECT 0.216 55.536 42.747 55.632 ;
      RECT 0.216 56.304 42.747 56.400 ;
      RECT 0.216 57.072 42.747 57.168 ;
      RECT 0.216 57.840 42.747 57.936 ;
      RECT 0.216 58.608 42.747 58.704 ;
      RECT 0.216 59.376 42.747 59.472 ;
      RECT 0.216 60.144 42.747 60.240 ;
      RECT 0.216 60.912 42.747 61.008 ;
      RECT 0.216 61.680 42.747 61.776 ;
      RECT 0.216 62.448 42.747 62.544 ;
      RECT 0.216 63.216 42.747 63.312 ;
      RECT 0.216 63.984 42.747 64.080 ;
      RECT 0.216 64.752 42.747 64.848 ;
      RECT 0.216 65.520 42.747 65.616 ;
      RECT 0.216 66.288 42.747 66.384 ;
      RECT 0.216 67.056 42.747 67.152 ;
      RECT 0.216 67.824 42.747 67.920 ;
      RECT 0.216 68.592 42.747 68.688 ;
      RECT 0.216 69.360 42.747 69.456 ;
      RECT 0.216 70.128 42.747 70.224 ;
      RECT 0.216 70.896 42.747 70.992 ;
      RECT 0.216 71.664 42.747 71.760 ;
      RECT 0.216 72.432 42.747 72.528 ;
      RECT 0.216 73.200 42.747 73.296 ;
      RECT 0.216 73.968 42.747 74.064 ;
      RECT 0.216 74.736 42.747 74.832 ;
      RECT 0.216 75.504 42.747 75.600 ;
      RECT 0.216 76.272 42.747 76.368 ;
      RECT 0.216 77.040 42.747 77.136 ;
      RECT 0.216 77.808 42.747 77.904 ;
      RECT 0.216 78.576 42.747 78.672 ;
      RECT 0.216 79.344 42.747 79.440 ;
      RECT 0.216 80.112 42.747 80.208 ;
      RECT 0.216 80.880 42.747 80.976 ;
      RECT 0.216 81.648 42.747 81.744 ;
      RECT 0.216 82.416 42.747 82.512 ;
      RECT 0.216 83.184 42.747 83.280 ;
      RECT 0.216 83.952 42.747 84.048 ;
      RECT 0.216 84.720 42.747 84.816 ;
      RECT 0.216 85.488 42.747 85.584 ;
      RECT 0.216 86.256 42.747 86.352 ;
      RECT 0.216 87.024 42.747 87.120 ;
      RECT 0.216 87.792 42.747 87.888 ;
      RECT 0.216 88.560 42.747 88.656 ;
      RECT 0.216 89.328 42.747 89.424 ;
      RECT 0.216 90.096 42.747 90.192 ;
      RECT 0.216 90.864 42.747 90.960 ;
      RECT 0.216 91.632 42.747 91.728 ;
      RECT 0.216 92.400 42.747 92.496 ;
      RECT 0.216 93.168 42.747 93.264 ;
      RECT 0.216 93.936 42.747 94.032 ;
      RECT 0.216 94.704 42.747 94.800 ;
      RECT 0.216 95.472 42.747 95.568 ;
      RECT 0.216 96.240 42.747 96.336 ;
      RECT 0.216 97.008 42.747 97.104 ;
      RECT 0.216 97.776 42.747 97.872 ;
      RECT 0.216 98.544 42.747 98.640 ;
      RECT 0.216 99.312 42.747 99.408 ;
      RECT 0.216 100.080 42.747 100.176 ;
      RECT 0.216 100.848 42.747 100.944 ;
      RECT 0.216 101.616 42.747 101.712 ;
      RECT 0.216 102.384 42.747 102.480 ;
      RECT 0.216 103.152 42.747 103.248 ;
      RECT 0.216 103.920 42.747 104.016 ;
      RECT 0.216 104.688 42.747 104.784 ;
      RECT 0.216 105.456 42.747 105.552 ;
    END
  END VDD
  OBS
    LAYER M1 ;
    RECT 0 0 42.963 105.938 ;
    LAYER M2 ;
    RECT 0 0 42.963 105.938 ;
    LAYER M3 ;
    RECT 0 0 42.963 105.938 ;
    LAYER M4 ;
    RECT 0 0 42.963 105.938 ;
  END
END fakeram_1rw1r_130w512d_sram

END LIBRARY
